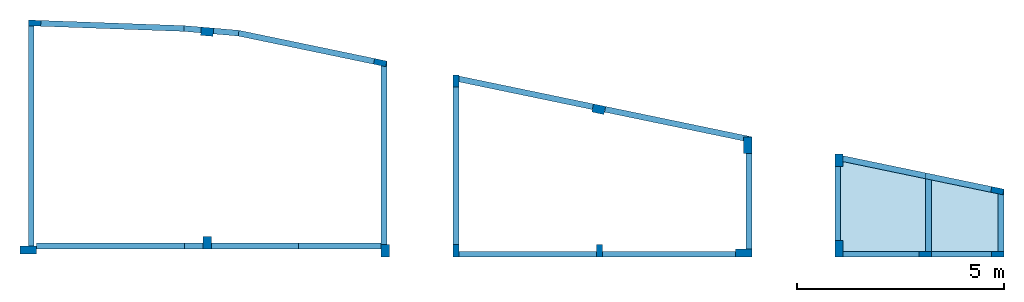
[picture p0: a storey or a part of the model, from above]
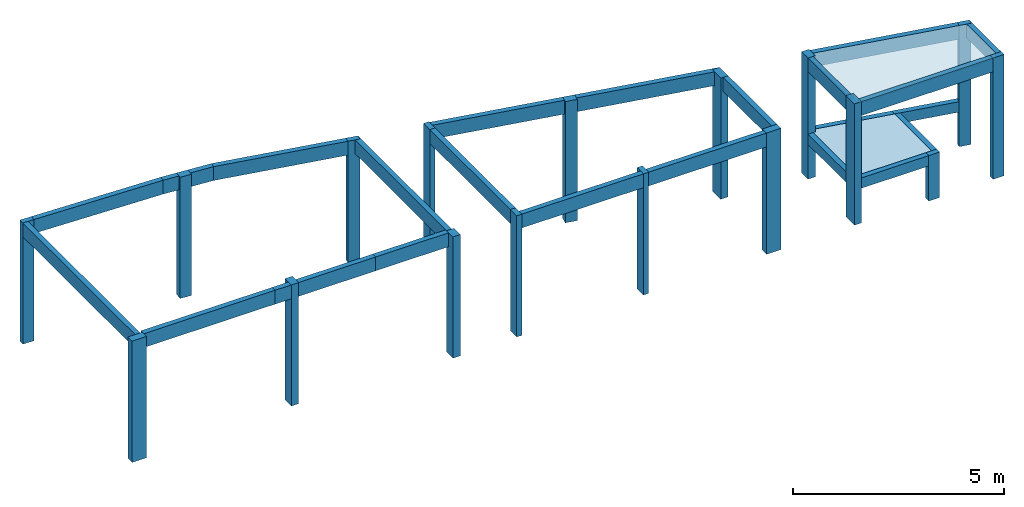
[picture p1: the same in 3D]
Properties of the parts of a building model (IFC4), part 1 of 2

# File
Description: IFC4
Time: 2026-06-03T07:09:51
Made in: IfcPlusPlus

# IfcBuildingStorey (6)
Name | LongName | Elevation (cm)
PÁTIO | PÁTIO | 0
TÉRREO | TÉRREO | 550
1º PAV. | 1º PAV. | 900
2º PAV. | 2º PAV. | 1250
3º PAV. | 3º PAV. | 1600
COBERTURA | COBERTURA | 1950

# IfcBeam (580)
Material: Concreto
Pset_ConcreteElementGeneral - ConcreteCover: 2.5 cm; ConstructionMethod: InSitu; ExposureClass: 2; StrengthClass: C-30
AltoQi_Eberick_Elemento - Elemento: Viga; Tipo: retangular
AltoQi_Eberick_Padrão - Cobrimento: 2.5 cm; Classe de concreto: C-30
AltoQi_Eberick_Cargas - Adicional (G2): 0; Solo (S): 0; Acidental (Q): 0; Água (A): 0; Subpressão (AS): 0
Pset_BeamCommon - IsExternal: yes; LoadBearing: yes
Name | In | Seção_bw (cm) | Seção_h (cm) | Elevação (cm) | Taxa de armadura | Ambiente | Cargas de parede (G2) | Reference
V.MURO1 | PÁTIO | 30 | 50 | 0 | 0.33 % | Contato com solo | 0 | Viga C-30 - Seção Retangular 30 X 50
V.MURO2 | PÁTIO | 30 | 50 | 0 | 0.33 % | Contato com solo | 0 | Viga C-30 - Seção Retangular 30 X 50
3 x V.MURO3 | PÁTIO | 30 | 50 | 0 | 0.33 % | Contato com solo | 0 | Viga C-30 - Seção Retangular 30 X 50
5 x V1 | PÁTIO | 20 | 60 | 0 | 0.20 % | Contato com solo | 1072.5 | Viga C-30 - Seção Retangular 20 X 60
V1 | PÁTIO | 20 | 60 | 0 | 0.26 % | Contato com solo | 1072.5 | Viga C-30 - Seção Retangular 20 X 60
V10 | PÁTIO | 14 | 50 | 0 | 0.22 % | Contato com solo | 1072.5 | Viga C-30 - Seção Retangular 14 X 50
4 x V11 | PÁTIO | 60 | 60 | 0 | 0.22 % | Contato com solo | 0 | Viga C-30 - Seção Retangular 60 X 60
2 x V12 | PÁTIO | 60 | 60 | 0 | 0.50 % | Contato com solo | 0 | Viga C-30 - Seção Retangular 60 X 60
V12 | PÁTIO | 60 | 60 | 0 | 0.61 % | Contato com solo | 0 | Viga C-30 - Seção Retangular 60 X 60
V12 | PÁTIO | 60 | 60 | 0 | 0.22 % | Contato com solo | 0 | Viga C-30 - Seção Retangular 60 X 60
V13 | PÁTIO | 40 | 50 | 0 | 0.40 % | Contato com solo | 1072.5 | Viga C-30 - Seção Retangular 40 X 50
V13 | PÁTIO | 40 | 50 | 0 | 0.50 % | Contato com solo | 1072.5 | Viga C-30 - Seção Retangular 40 X 50
V14 | PÁTIO | 50 | 60 | 0 | 0.16 % | Contato com solo | 0 | Viga C-30 - Seção Retangular 50 X 60
2 x V14 | PÁTIO | 50 | 60 | 0 | 0.47 % | Contato com solo | 0 | Viga C-30 - Seção Retangular 50 X 60
V15 | PÁTIO | 50 | 60 | 0 | 0.27 % | Contato com solo | 1072.5 | Viga C-30 - Seção Retangular 50 X 60
V15 | PÁTIO | 50 | 60 | 0 | 0.47 % | Contato com solo | 1072.5 | Viga C-30 - Seção Retangular 50 X 60
2 x V16 | PÁTIO | 50 | 60 | 0 | 0.47 % | Contato com solo | 0 | Viga C-30 - Seção Retangular 50 X 60
V16 | PÁTIO | 50 | 60 | 0 | 0.16 % | Contato com solo | 0 | Viga C-30 - Seção Retangular 50 X 60
V17 | PÁTIO | 14 | 50 | 0 | 0.86 % | Contato com solo | 0 | Viga C-30 - Seção Retangular 14 X 50
V18 | PÁTIO | 50 | 60 | 0 | 0.54 % | Contato com solo | 1072.5 | Viga C-30 - Seção Retangular 50 X 60
V18 | PÁTIO | 50 | 60 | 0 | 0.27 % | Contato com solo | 1072.5 | Viga C-30 - Seção Retangular 50 X 60
2 x V19 | PÁTIO | 30 | 70 | 0 | 0.48 % | Contato com solo | 0 | Viga C-30 - Seção Retangular 30 X 70
V19 | PÁTIO | 30 | 50 | 0 | 0.54 % | Contato com solo | 0 | Viga C-30 - Seção Retangular 30 X 50
V19 | PÁTIO | 30 | 70 | 0 | 0.23 % | Contato com solo | 0 | Viga C-30 - Seção Retangular 30 X 70
V2 | PÁTIO | 20 | 50 | 0 | 0.16 % | Contato com solo | 0 | Viga C-30 - Seção Retangular 20 X 50
2 x V20 | PÁTIO | 30 | 50 | 0 | 0.16 % | Contato com solo | 1072.5 | Viga C-30 - Seção Retangular 30 X 50
V20 | PÁTIO | 30 | 70 | 0 | 0.18 % | Contato com solo | 1072.5 | Viga C-30 - Seção Retangular 30 X 70
2 x V20 | PÁTIO | 30 | 70 | 0 | 0.23 % | Contato com solo | 1072.5 | Viga C-30 - Seção Retangular 30 X 70
2 x V21 | PÁTIO | 20 | 50 | 0 | 0.16 % | Contato com solo | 0 | Viga C-30 - Seção Retangular 20 X 50
2 x V22 | PÁTIO | 40 | 60 | 0 | 0.20 % | Contato com solo | 0 | Viga C-30 - Seção Retangular 40 X 60
V23 | PÁTIO | 14 | 50 | 0 | 0.22 % | Externo | 682.5 | Viga C-30 - Seção Retangular 14 X 50
V24 | PÁTIO | 20 | 170 | 0 | 0.14 % | Contato com solo | 1072.5 | Viga C-30 - Seção Retangular 20 X 170
V24 | PÁTIO | 20 | 80 | 0 | 0.15 % | Contato com solo | 1072.5 | Viga C-30 - Seção Retangular 20 X 80
2 x V25 | PÁTIO | 40 | 60 | 0 | 0.59 % | Contato com solo | 0 | Viga C-30 - Seção Retangular 40 X 60
V25 | PÁTIO | 40 | 60 | 0 | 0.34 % | Contato com solo | 0 | Viga C-30 - Seção Retangular 40 X 60
2 x V26 | PÁTIO | 20 | 60 | 0 | 0.41 % | Contato com solo | 0 | Viga C-30 - Seção Retangular 20 X 60
V27 | PÁTIO | 20 | 170 | 0 | 0.16 % | Contato com solo | 1072.5 | Viga C-30 - Seção Retangular 20 X 170
2 x V28 | PÁTIO | 50 | 60 | 0 | 0.67 % | Contato com solo | 0 | Viga C-30 - Seção Retangular 50 X 60
V28 | PÁTIO | 50 | 60 | 0 | 0.16 % | Contato com solo | 0 | Viga C-30 - Seção Retangular 50 X 60
V28 | PÁTIO | 50 | 60 | 0 | 0.27 % | Contato com solo | 0 | Viga C-30 - Seção Retangular 50 X 60
V29 | PÁTIO | 50 | 60 | 0 | 0.16 % | Contato com solo | 0 | Viga C-30 - Seção Retangular 50 X 60
2 x V29 | PÁTIO | 50 | 60 | 0 | 0.47 % | Contato com solo | 0 | Viga C-30 - Seção Retangular 50 X 60
V29 | PÁTIO | 50 | 60 | 0 | 0.27 % | Contato com solo | 0 | Viga C-30 - Seção Retangular 50 X 60
2 x V3 | PÁTIO | 20 | 170 | 0 | 0.35 % | Contato com solo | 1072.5 | Viga C-30 - Seção Retangular 20 X 170
V3 | PÁTIO | 20 | 70 | 0 | 0.43 % | Contato com solo | 1072.5 | Viga C-30 - Seção Retangular 20 X 70
V3 | PÁTIO | 20 | 70 | 0 | 0.29 % | Contato com solo | 1072.5 | Viga C-30 - Seção Retangular 20 X 70
V3 | PÁTIO | 20 | 50 | 0 | 0.40 % | Contato com solo | 1072.5 | Viga C-30 - Seção Retangular 20 X 50
V30 | PÁTIO | 70 | 60 | 0 | 0.29 % | Contato com solo | 0 | Viga C-30 - Seção Retangular 70 X 60
V30 | PÁTIO | 70 | 60 | 0 | 0.53 % | Contato com solo | 0 | Viga C-30 - Seção Retangular 70 X 60
2 x V31 | PÁTIO | 20 | 50 | 0 | 0.40 % | Contato com solo | 1072.5 | Viga C-30 - Seção Retangular 20 X 50
V31 | PÁTIO | 20 | 170 | 0 | 0.18 % | Contato com solo | 1072.5 | Viga C-30 - Seção Retangular 20 X 170
V32 | PÁTIO | 14 | 50 | 0 | 0.22 % | Contato com solo | 1072.5 | Viga C-30 - Seção Retangular 14 X 50
V33 | PÁTIO | 60 | 60 | 0 | 0.45 % | Contato com solo | 0 | Viga C-30 - Seção Retangular 60 X 60
V33 | PÁTIO | 60 | 60 | 0 | 0.22 % | Contato com solo | 0 | Viga C-30 - Seção Retangular 60 X 60
3 x V34 | PÁTIO | 14 | 50 | 0 | 0.35 % | Contato com solo | 1072.5 | Viga C-30 - Seção Retangular 14 X 50
2 x V4 | PÁTIO | 20 | 50 | 0 | 0.24 % | Contato com solo | 0 | Viga C-30 - Seção Retangular 20 X 50
V4 | PÁTIO | 20 | 50 | 0 | 0.16 % | Contato com solo | 0 | Viga C-30 - Seção Retangular 20 X 50
V5 | PÁTIO | 14 | 50 | 0 | 0.22 % | Contato com solo | 0 | Viga C-30 - Seção Retangular 14 X 50
3 x V6 | PÁTIO | 14 | 50 | 0 | 0.22 % | Contato com solo | 0 | Viga C-30 - Seção Retangular 14 X 50
V6 | PÁTIO | 14 | 50 | 0 | 0.34 % | Contato com solo | 0 | Viga C-30 - Seção Retangular 14 X 50
2 x V7 | PÁTIO | 14 | 50 | 0 | 0.22 % | Contato com solo | 0 | Viga C-30 - Seção Retangular 14 X 50
V8 | PÁTIO | 14 | 50 | 0 | 0.22 % | Contato com solo | 0 | Viga C-30 - Seção Retangular 14 X 50
2 x V9 | PÁTIO | 14 | 50 | 0 | 0.22 % | Externo | 682.5 | Viga C-30 - Seção Retangular 14 X 50
2 x V.ESCADA1 | TÉRREO | 14 | 50 | 0 | 0.22 % | Contato com solo | 585 | Viga C-30 - Seção Retangular 14 X 50
V.ESCADA2 | TÉRREO | 14 | 50 | 0 | 0.22 % | Contato com solo | 585 | Viga C-30 - Seção Retangular 14 X 50
2 x V.MURO1 | TÉRREO | 20 | 60 | 0 | 0.20 % | Externo | 585 | Viga C-30 - Seção Retangular 20 X 60
V.MURO2 | TÉRREO | 20 | 50 | 0 | 0.16 % | Externo | 585 | Viga C-30 - Seção Retangular 20 X 50
2 x V.MURO3 | TÉRREO | 20 | 50 | 0 | 0.40 % | Externo | 0 | Viga C-30 - Seção Retangular 20 X 50
V.MURO4 | TÉRREO | 20 | 50 | 0 | 0.40 % | Externo | 0 | Viga C-30 - Seção Retangular 20 X 50
V.RAMPA1 | TÉRREO | 20 | 50 | 0 | 0.16 % | Externo | 0 | Viga C-30 - Seção Retangular 20 X 50
V.RAMPA10 | TÉRREO | 20 | 40 | 0 | 0.20 % | Externo | 0 | Viga C-30 - Seção Retangular 20 X 40
2 x V.RAMPA11 | TÉRREO | 20 | 50 | 0 | 0.31 % | Externo | 585 | Viga C-30 - Seção Retangular 20 X 50
2 x V.RAMPA11 | TÉRREO | 20 | 40 | 0 | 0.39 % | Externo | 0 | Viga C-30 - Seção Retangular 20 X 40
V.RAMPA12 | TÉRREO | 20 | 40 | 0 | 0.20 % | Externo | 0 | Viga C-30 - Seção Retangular 20 X 40
2 x V.RAMPA13 | TÉRREO | 20 | 50 | 0 | 0.49 % | Externo | 0 | Viga C-30 - Seção Retangular 20 X 50
V.RAMPA2 | TÉRREO | 20 | 50 | 0 | 0.31 % | Externo | 0 | Viga C-30 - Seção Retangular 20 X 50
2 x V.RAMPA3 | TÉRREO | 40 | 25 | 0 | 0.49 % | Externo | 0 | Viga C-30 - Seção Retangular 40 X 25
V.RAMPA4 | TÉRREO | 20 | 50 | 0 | 0.24 % | Externo | 0 | Viga C-30 - Seção Retangular 20 X 50
V.RAMPA5 | TÉRREO | 20 | 40 | 0 | 0.39 % | Externo | 0 | Viga C-30 - Seção Retangular 20 X 40
2 x V.RAMPA6 | TÉRREO | 20 | 40 | 0 | 0.29 % | Externo | 0 | Viga C-30 - Seção Retangular 20 X 40
2 x V.RAMPA7 | TÉRREO | 20 | 50 | 0 | 0.24 % | Externo | 0 | Viga C-30 - Seção Retangular 20 X 50
3 x V.RAMPA8 | TÉRREO | 20 | 50 | 0 | 0.37 % | Externo | 0 | Viga C-30 - Seção Retangular 20 X 50
V.RAMPA9 | TÉRREO | 20 | 40 | 0 | 0.20 % | Externo | 0 | Viga C-30 - Seção Retangular 20 X 40
V1 | TÉRREO | 14 | 50 | 0 | 0.22 % | Externo | 682.5 | Viga C-30 - Seção Retangular 14 X 50
4 x V10 | TÉRREO | 20 | 50 | 0 | 0.60 % | Externo | 0 | Viga C-30 - Seção Retangular 20 X 50
V11 | TÉRREO | 25 | 50 | 0 | 0.29 % | Externo | 682.5 | Viga C-30 - Seção Retangular 25 X 50
V11 | TÉRREO | 25 | 50 | 0 | 0.39 % | Externo | 682.5 | Viga C-30 - Seção Retangular 25 X 50
V11 | TÉRREO | 14 | 50 | 0 | 0.35 % | Externo | 682.5 | Viga C-30 - Seção Retangular 14 X 50
V12 | TÉRREO | 14 | 50 | 0 | 0.22 % | Externo | 682.5 | Viga C-30 - Seção Retangular 14 X 50
V13 | TÉRREO | 14 | 50 | 0 | 0.22 % | Externo | 682.5 | Viga C-30 - Seção Retangular 14 X 50
V14 | TÉRREO | 14 | 50 | 0 | 0.22 % | Externo | 682.5 | Viga C-30 - Seção Retangular 14 X 50
V15 | TÉRREO | 20 | 50 | 0 | 0.37 % | Externo | 0 | Viga C-30 - Seção Retangular 20 X 50
V15 | TÉRREO | 20 | 50 | 0 | 0.37 % | Externo | 682.5 | Viga C-30 - Seção Retangular 20 X 50
V16 | TÉRREO | 14 | 50 | 0 | 0.22 % | Externo | 682.5 | Viga C-30 - Seção Retangular 14 X 50
V17 | TÉRREO | 14 | 50 | 0 | 0.22 % | Externo | 682.5 | Viga C-30 - Seção Retangular 14 X 50
3 x V18 | TÉRREO | 14 | 50 | 0 | 0.35 % | Externo | 682.5 | Viga C-30 - Seção Retangular 14 X 50
V18 | TÉRREO | 14 | 50 | 0 | 0.53 % | Externo | 682.5 | Viga C-30 - Seção Retangular 14 X 50
V18 | TÉRREO | 14 | 50 | 0 | 0.70 % | Externo | 682.5 | Viga C-30 - Seção Retangular 14 X 50
V19 | TÉRREO | 14 | 50 | 0 | 0.22 % | Externo | 682.5 | Viga C-30 - Seção Retangular 14 X 50
2 x V2 | TÉRREO | 14 | 50 | 0 | 0.53 % | Externo | 682.5 | Viga C-30 - Seção Retangular 14 X 50
V20 | TÉRREO | 14 | 50 | 0 | 0.22 % | Externo | 682.5 | Viga C-30 - Seção Retangular 14 X 50
V21 | TÉRREO | 14 | 50 | 0 | 0.22 % | Externo | 682.5 | Viga C-30 - Seção Retangular 14 X 50
2 x V22 | TÉRREO | 14 | 50 | 0 | 0.22 % | Externo | 0 | Viga C-30 - Seção Retangular 14 X 50
2 x V23 | TÉRREO | 14 | 50 | 0 | 0.34 % | Externo | 682.5 | Viga C-30 - Seção Retangular 14 X 50
V23 | TÉRREO | 14 | 50 | 0 | 0.22 % | Externo | 682.5 | Viga C-30 - Seção Retangular 14 X 50
V24 | TÉRREO | 14 | 50 | 0 | 0.34 % | Externo | 682.5 | Viga C-30 - Seção Retangular 14 X 50
2 x V25 | TÉRREO | 14 | 50 | 0 | 0.53 % | Externo | 682.5 | Viga C-30 - Seção Retangular 14 X 50
2 x V26 | TÉRREO | 14 | 50 | 0 | 0.53 % | Externo | 682.5 | Viga C-30 - Seção Retangular 14 X 50
3 x V27 | TÉRREO | 14 | 50 | 0 | 0.53 % | Externo | 682.5 | Viga C-30 - Seção Retangular 14 X 50
2 x V28 | TÉRREO | 14 | 50 | 0 | 0.53 % | Externo | 682.5 | Viga C-30 - Seção Retangular 14 X 50
V29 | TÉRREO | 14 | 50 | 0 | 0.35 % | Externo | 682.5 | Viga C-30 - Seção Retangular 14 X 50
3 x V3 | TÉRREO | 20 | 50 | 0 | 0.37 % | Externo | 682.5 | Viga C-30 - Seção Retangular 20 X 50
V3 | TÉRREO | 20 | 50 | 0 | 0.24 % | Externo | 682.5 | Viga C-30 - Seção Retangular 20 X 50
V3 | TÉRREO | 20 | 50 | 0 | 0.16 % | Externo | 682.5 | Viga C-30 - Seção Retangular 20 X 50
2 x V3 | TÉRREO | 20 | 50 | 0 | 0.25 % | Externo | 682.5 | Viga C-30 - Seção Retangular 20 X 50
2 x V30 | TÉRREO | 20 | 50 | 0 | 0.16 % | Externo | 682.5 | Viga C-30 - Seção Retangular 20 X 50
2 x V30 | TÉRREO | 20 | 50 | 0 | 0.24 % | Externo | 682.5 | Viga C-30 - Seção Retangular 20 X 50
2 x V31 | TÉRREO | 20 | 50 | 0 | 0.37 % | Externo | 0 | Viga C-30 - Seção Retangular 20 X 50
V31 | TÉRREO | 20 | 50 | 0 | 0.25 % | Externo | 0 | Viga C-30 - Seção Retangular 20 X 50
V32 | TÉRREO | 14 | 50 | 0 | 0.22 % | Externo | 0 | Viga C-30 - Seção Retangular 14 X 50
V33 | TÉRREO | 14 | 50 | 0 | 0.22 % | Externo | 682.5 | Viga C-30 - Seção Retangular 14 X 50
V34 | TÉRREO | 14 | 50 | 0 | 0.22 % | Externo | 682.5 | Viga C-30 - Seção Retangular 14 X 50
V34 | TÉRREO | 14 | 50 | 0 | 0.34 % | Externo | 682.5 | Viga C-30 - Seção Retangular 14 X 50
V35 | TÉRREO | 14 | 50 | 0 | 0.86 % | Externo | 682.5 | Viga C-30 - Seção Retangular 14 X 50
2 x V36 | TÉRREO | 14 | 50 | 0 | 0.86 % | Externo | 682.5 | Viga C-30 - Seção Retangular 14 X 50
2 x V36 | TÉRREO | 14 | 50 | 0 | 0.53 % | Externo | 682.5 | Viga C-30 - Seção Retangular 14 X 50
V37 | TÉRREO | 14 | 50 | 0 | 0.22 % | Externo | 682.5 | Viga C-30 - Seção Retangular 14 X 50
V38 | TÉRREO | 14 | 50 | 0 | 0.22 % | Externo | 682.5 | Viga C-30 - Seção Retangular 14 X 50
V39 | TÉRREO | 14 | 50 | 0 | 0.22 % | Externo | 682.5 | Viga C-30 - Seção Retangular 14 X 50
V4 | TÉRREO | 14 | 50 | 0 | 0.22 % | Externo | 0 | Viga C-30 - Seção Retangular 14 X 50
4 x V40 | TÉRREO | 14 | 50 | 0 | 0.53 % | Externo | 682.5 | Viga C-30 - Seção Retangular 14 X 50
V41 | TÉRREO | 14 | 50 | 0 | 0.35 % | Externo | 682.5 | Viga C-30 - Seção Retangular 14 X 50
6 x V41 | TÉRREO | 14 | 50 | 0 | 0.70 % | Externo | 682.5 | Viga C-30 - Seção Retangular 14 X 50
2 x V42 | TÉRREO | 14 | 50 | 0 | 0.53 % | Externo | 682.5 | Viga C-30 - Seção Retangular 14 X 50
V42 | TÉRREO | 14 | 50 | 0 | 0.35 % | Externo | 682.5 | Viga C-30 - Seção Retangular 14 X 50
4 x V42 | TÉRREO | 14 | 50 | 0 | 0.22 % | Externo | 682.5 | Viga C-30 - Seção Retangular 14 X 50
3 x V43 | TÉRREO | 14 | 50 | 0 | 0.22 % | Externo | 682.5 | Viga C-30 - Seção Retangular 14 X 50
V43 | TÉRREO | 14 | 50 | 0 | 0.34 % | Externo | 682.5 | Viga C-30 - Seção Retangular 14 X 50
V44 | TÉRREO | 30 | 50 | 0 | 0.16 % | Externo | 0 | Viga C-30 - Seção Retangular 30 X 50
2 x V44 | TÉRREO | 30 | 50 | 0 | 0.33 % | Externo | 0 | Viga C-30 - Seção Retangular 30 X 50
5 x V45 | TÉRREO | 14 | 50 | 0 | 0.35 % | Externo | 682.5 | Viga C-30 - Seção Retangular 14 X 50
3 x V5 | TÉRREO | 20 | 50 | 0 | 0.37 % | Externo | 682.5 | Viga C-30 - Seção Retangular 20 X 50
2 x V5 | TÉRREO | 20 | 50 | 0 | 0.25 % | Externo | 682.5 | Viga C-30 - Seção Retangular 20 X 50
2 x V6 | TÉRREO | 14 | 50 | 0 | 0.22 % | Externo | 682.5 | Viga C-30 - Seção Retangular 14 X 50
2 x V7 | TÉRREO | 14 | 50 | 0 | 0.86 % | Externo | 682.5 | Viga C-30 - Seção Retangular 14 X 50
2 x V8 | TÉRREO | 14 | 50 | 0 | 0.53 % | Externo | 0 | Viga C-30 - Seção Retangular 14 X 50
2 x V9 | TÉRREO | 14 | 50 | 0 | 0.22 % | Externo | 0 | Viga C-30 - Seção Retangular 14 X 50
2 x V.ESCADA1 | 1º PAV. | 14 | 50 | 0 | 0.22 % | Externo | 585 | Viga C-30 - Seção Retangular 14 X 50
V.ESCADA2 | 1º PAV. | 14 | 50 | 0 | 0.22 % | Externo | 0 | Viga C-30 - Seção Retangular 14 X 50
V.MURO1 | 1º PAV. | 14 | 40 | -100 | 0.28 % | Externo | 0 | Viga C-30 - Seção Retangular 14 X 40
V.MURO2 | 1º PAV. | 14 | 40 | -100 | 0.28 % | Externo | 0 | Viga C-30 - Seção Retangular 14 X 40
V.MURO3 | 1º PAV. | 20 | 60 | -40 | 0.51 % | Externo | 0 | Viga C-30 - Seção Retangular 20 X 60
V.MURO4 | 1º PAV. | 14 | 40 | -100 | 0.28 % | Externo | 585 | Viga C-30 - Seção Retangular 14 X 40
V.MURO5 | 1º PAV. | 14 | 40 | -100 | 0.28 % | Externo | 0 | Viga C-30 - Seção Retangular 14 X 40
V1 | 1º PAV. | 14 | 50 | 0 | 0.22 % | Externo | 682.5 | Viga C-30 - Seção Retangular 14 X 50
V10 | 1º PAV. | 20 | 50 | 0 | 0.49 % | Externo | 682.5 | Viga C-30 - Seção Retangular 20 X 50
V10 | 1º PAV. | 20 | 50 | 0 | 0.37 % | Externo | 682.5 | Viga C-30 - Seção Retangular 20 X 50
V11 | 1º PAV. | 14 | 50 | 0 | 0.22 % | Externo | 682.5 | Viga C-30 - Seção Retangular 14 X 50
V12 | 1º PAV. | 14 | 50 | 0 | 0.22 % | Externo | 0 | Viga C-30 - Seção Retangular 14 X 50
V13 | 1º PAV. | 20 | 50 | 0 | 0.37 % | Externo | 682.5 | Viga C-30 - Seção Retangular 20 X 50
3 x V13 | 1º PAV. | 20 | 50 | 0 | 0.49 % | Externo | 0 | Viga C-30 - Seção Retangular 20 X 50
V13 | 1º PAV. | 20 | 50 | 0 | 0.37 % | Externo | 0 | Viga C-30 - Seção Retangular 20 X 50
V13 | 1º PAV. | 20 | 50 | 0 | 0.25 % | Externo | 682.5 | Viga C-30 - Seção Retangular 20 X 50
V14 | 1º PAV. | 14 | 50 | 0 | 0.22 % | Externo | 682.5 | Viga C-30 - Seção Retangular 14 X 50
V15 | 1º PAV. | 14 | 70 | 0 | 0.16 % | Externo | 682.5 | Viga C-30 - Seção Retangular 14 X 70
V16 | 1º PAV. | 14 | 50 | 0 | 0.22 % | Externo | 682.5 | Viga C-30 - Seção Retangular 14 X 50
V17 | 1º PAV. | 14 | 70 | 0 | 0.16 % | Externo | 682.5 | Viga C-30 - Seção Retangular 14 X 70
V18 | 1º PAV. | 14 | 50 | 0 | 0.22 % | Externo | 682.5 | Viga C-30 - Seção Retangular 14 X 50
V19 | 1º PAV. | 14 | 50 | 0 | 0.53 % | Externo | 682.5 | Viga C-30 - Seção Retangular 14 X 50
V19 | 1º PAV. | 14 | 50 | 0 | 0.53 % | Externo | 0 | Viga C-30 - Seção Retangular 14 X 50
V2 | 1º PAV. | 20 | 50 | 0 | 0.37 % | Externo | 682.5 | Viga C-30 - Seção Retangular 20 X 50
V2 | 1º PAV. | 20 | 70 | 0 | 0.18 % | Externo | 682.5 | Viga C-30 - Seção Retangular 20 X 70
V20 | 1º PAV. | 14 | 50 | 0 | 0.22 % | Externo | 682.5 | Viga C-30 - Seção Retangular 14 X 50
V21 | 1º PAV. | 14 | 70 | 0 | 0.16 % | Externo | 682.5 | Viga C-30 - Seção Retangular 14 X 70
V22 | 1º PAV. | 14 | 50 | 0 | 0.22 % | Externo | 682.5 | Viga C-30 - Seção Retangular 14 X 50
V23 | 1º PAV. | 14 | 70 | 0 | 0.16 % | Externo | 682.5 | Viga C-30 - Seção Retangular 14 X 70
V24 | 1º PAV. | 20 | 70 | 0 | 0.17 % | Externo | 682.5 | Viga C-30 - Seção Retangular 20 X 70
V24 | 1º PAV. | 20 | 50 | 0 | 0.24 % | Externo | 682.5 | Viga C-30 - Seção Retangular 20 X 50
V24 | 1º PAV. | 20 | 50 | 0 | 0.37 % | Externo | 682.5 | Viga C-30 - Seção Retangular 20 X 50
V25 | 1º PAV. | 14 | 50 | 0 | 0.57 % | Externo | 682.5 | Viga C-30 - Seção Retangular 14 X 50
V25 | 1º PAV. | 14 | 50 | 0 | 0.53 % | Externo | 682.5 | Viga C-30 - Seção Retangular 14 X 50
V26 | 1º PAV. | 14 | 50 | 0 | 0.22 % | Externo | 682.5 | Viga C-30 - Seção Retangular 14 X 50
V27 | 1º PAV. | 14 | 50 | 0 | 0.22 % | Externo | 682.5 | Viga C-30 - Seção Retangular 14 X 50
8 x V28 | 1º PAV. | 20 | 70 | 0 | 0.86 % | Externo | 682.5 | Viga C-30 - Seção Retangular 20 X 70
3 x V29 | 1º PAV. | 40 | 60 | 0 | 0.20 % | Externo | 0 | Viga C-30 - Seção Retangular 40 X 60
4 x V3 | 1º PAV. | 20 | 50 | 0 | 0.25 % | Externo | 682.5 | Viga C-30 - Seção Retangular 20 X 50
3 x V3 | 1º PAV. | 20 | 50 | 0 | 0.37 % | Externo | 682.5 | Viga C-30 - Seção Retangular 20 X 50
2 x V30 | 1º PAV. | 14 | 50 | 0 | 0.34 % | Externo | 682.5 | Viga C-30 - Seção Retangular 14 X 50
V31 | 1º PAV. | 14 | 50 | 0 | 0.34 % | Externo | 682.5 | Viga C-30 - Seção Retangular 14 X 50
2 x V32 | 1º PAV. | 14 | 50 | 0 | 0.45 % | Externo | 682.5 | Viga C-30 - Seção Retangular 14 X 50
2 x V33 | 1º PAV. | 14 | 50 | 0 | 0.53 % | Externo | 682.5 | Viga C-30 - Seção Retangular 14 X 50
3 x V34 | 1º PAV. | 14 | 50 | 0 | 0.53 % | Externo | 682.5 | Viga C-30 - Seção Retangular 14 X 50
2 x V35 | 1º PAV. | 14 | 50 | 0 | 0.53 % | Externo | 682.5 | Viga C-30 - Seção Retangular 14 X 50
V36 | 1º PAV. | 14 | 50 | 0 | 0.22 % | Externo | 682.5 | Viga C-30 - Seção Retangular 14 X 50
2 x V37 | 1º PAV. | 20 | 50 | 0 | 0.24 % | Externo | 682.5 | Viga C-30 - Seção Retangular 20 X 50
V37 | 1º PAV. | 20 | 50 | 0 | 0.16 % | Externo | 682.5 | Viga C-30 - Seção Retangular 20 X 50
3 x V38 | 1º PAV. | 20 | 50 | 0 | 0.25 % | Externo | 0 | Viga C-30 - Seção Retangular 20 X 50
V39 | 1º PAV. | 14 | 50 | 0 | 0.22 % | Externo | 0 | Viga C-30 - Seção Retangular 14 X 50
V4 | 1º PAV. | 14 | 50 | 0 | 0.22 % | Externo | 0 | Viga C-30 - Seção Retangular 14 X 50
V40 | 1º PAV. | 14 | 50 | 0 | 0.22 % | Externo | 682.5 | Viga C-30 - Seção Retangular 14 X 50
V41 | 1º PAV. | 14 | 50 | 0 | 0.22 % | Externo | 682.5 | Viga C-30 - Seção Retangular 14 X 50
V42 | 1º PAV. | 14 | 50 | 0 | 0.53 % | Externo | 682.5 | Viga C-30 - Seção Retangular 14 X 50
V43 | 1º PAV. | 14 | 50 | 0 | 0.34 % | Externo | 682.5 | Viga C-30 - Seção Retangular 14 X 50
2 x V43 | 1º PAV. | 14 | 50 | 0 | 0.45 % | Externo | 682.5 | Viga C-30 - Seção Retangular 14 X 50
V44 | 1º PAV. | 14 | 50 | 0 | 0.22 % | Externo | 682.5 | Viga C-30 - Seção Retangular 14 X 50
V45 | 1º PAV. | 14 | 50 | 0 | 0.22 % | Externo | 682.5 | Viga C-30 - Seção Retangular 14 X 50
V46 | 1º PAV. | 14 | 50 | 0 | 0.22 % | Externo | 682.5 | Viga C-30 - Seção Retangular 14 X 50
2 x V47 | 1º PAV. | 14 | 50 | 0 | 0.53 % | Externo | 682.5 | Viga C-30 - Seção Retangular 14 X 50
2 x V47 | 1º PAV. | 14 | 50 | 0 | 0.35 % | Externo | 682.5 | Viga C-30 - Seção Retangular 14 X 50
6 x V48 | 1º PAV. | 14 | 50 | 0 | 0.70 % | Externo | 682.5 | Viga C-30 - Seção Retangular 14 X 50
V48 | 1º PAV. | 14 | 50 | 0 | 0.35 % | Externo | 682.5 | Viga C-30 - Seção Retangular 14 X 50
4 x V49 | 1º PAV. | 14 | 50 | 0 | 0.22 % | Externo | 682.5 | Viga C-30 - Seção Retangular 14 X 50
2 x V49 | 1º PAV. | 14 | 50 | 0 | 0.53 % | Externo | 682.5 | Viga C-30 - Seção Retangular 14 X 50
V49 | 1º PAV. | 14 | 50 | 0 | 0.35 % | Externo | 682.5 | Viga C-30 - Seção Retangular 14 X 50
5 x V5 | 1º PAV. | 20 | 50 | 0 | 0.16 % | Externo | 682.5 | Viga C-30 - Seção Retangular 20 X 50
4 x V50 | 1º PAV. | 14 | 50 | 0 | 0.34 % | Externo | 682.5 | Viga C-30 - Seção Retangular 14 X 50
V51 | 1º PAV. | 30 | 50 | 0 | 0.33 % | Externo | 0 | Viga C-30 - Seção Retangular 30 X 50
2 x V51 | 1º PAV. | 30 | 50 | 0 | 0.16 % | Externo | 0 | Viga C-30 - Seção Retangular 30 X 50
4 x V52 | 1º PAV. | 14 | 50 | 0 | 0.35 % | Externo | 682.5 | Viga C-30 - Seção Retangular 14 X 50
V52 | 1º PAV. | 14 | 50 | 0 | 0.22 % | Externo | 682.5 | Viga C-30 - Seção Retangular 14 X 50
V6 | 1º PAV. | 14 | 70 | 0 | 0.16 % | Externo | 682.5 | Viga C-30 - Seção Retangular 14 X 70
V7 | 1º PAV. | 14 | 70 | 0 | 0.16 % | Externo | 682.5 | Viga C-30 - Seção Retangular 14 X 70
V8 | 1º PAV. | 14 | 70 | 0 | 0.16 % | Externo | 682.5 | Viga C-30 - Seção Retangular 14 X 70
3 x V9 | 1º PAV. | 14 | 50 | 0 | 0.53 % | Externo | 0 | Viga C-30 - Seção Retangular 14 X 50
2 x V.ESCADA1 | 2º PAV. | 14 | 50 | 0 | 0.22 % | Externo | 585 | Viga C-30 - Seção Retangular 14 X 50
V.ESCADA2 | 2º PAV. | 14 | 50 | 0 | 0.22 % | Externo | 585 | Viga C-30 - Seção Retangular 14 X 50
V.INCLINADA1 | 2º PAV. | 20 | 50 | 0 | 0.31 % | Externo | 0 | Viga C-30 - Seção Retangular 20 X 50
V.INCLINADA2 | 2º PAV. | 20 | 50 | 0 | 0.31 % | Externo | 0 | Viga C-30 - Seção Retangular 20 X 50
V1 | 2º PAV. | 14 | 50 | 0 | 0.22 % | Externo | 682.5 | Viga C-30 - Seção Retangular 14 X 50
V10 | 2º PAV. | 20 | 50 | 0 | 0.49 % | Externo | 682.5 | Viga C-30 - Seção Retangular 20 X 50
V10 | 2º PAV. | 20 | 50 | 0 | 0.37 % | Externo | 682.5 | Viga C-30 - Seção Retangular 20 X 50
V11 | 2º PAV. | 14 | 50 | 0 | 0.22 % | Externo | 682.5 | Viga C-30 - Seção Retangular 14 X 50
V12 | 2º PAV. | 14 | 50 | 0 | 0.22 % | Externo | 0 | Viga C-30 - Seção Retangular 14 X 50
2 x V13 | 2º PAV. | 25 | 50 | 0 | 0.32 % | Externo | 0 | Viga C-30 - Seção Retangular 25 X 50
4 x V13 | 2º PAV. | 25 | 50 | 0 | 0.48 % | Externo | 0 | Viga C-30 - Seção Retangular 25 X 50
V14 | 2º PAV. | 14 | 50 | 0 | 0.22 % | Externo | 682.5 | Viga C-30 - Seção Retangular 14 X 50
V15 | 2º PAV. | 14 | 50 | 0 | 0.22 % | Externo | 682.5 | Viga C-30 - Seção Retangular 14 X 50
V16 | 2º PAV. | 14 | 50 | 0 | 0.22 % | Externo | 682.5 | Viga C-30 - Seção Retangular 14 X 50
V17 | 2º PAV. | 14 | 50 | 0 | 0.22 % | Externo | 682.5 | Viga C-30 - Seção Retangular 14 X 50
V18 | 2º PAV. | 14 | 50 | 0 | 0.22 % | Externo | 682.5 | Viga C-30 - Seção Retangular 14 X 50
V19 | 2º PAV. | 14 | 50 | 0 | 0.45 % | Externo | 0 | Viga C-30 - Seção Retangular 14 X 50
V19 | 2º PAV. | 14 | 50 | 0 | 0.45 % | Externo | 682.5 | Viga C-30 - Seção Retangular 14 X 50
V2 | 2º PAV. | 20 | 50 | 0 | 0.49 % | Externo | 682.5 | Viga C-30 - Seção Retangular 20 X 50
2 x V2 | 2º PAV. | 20 | 50 | 0 | 0.86 % | Externo | 682.5 | Viga C-30 - Seção Retangular 20 X 50
V20 | 2º PAV. | 14 | 50 | 0 | 0.22 % | Externo | 682.5 | Viga C-30 - Seção Retangular 14 X 50
V21 | 2º PAV. | 14 | 50 | 0 | 0.22 % | Externo | 682.5 | Viga C-30 - Seção Retangular 14 X 50
V22 | 2º PAV. | 14 | 50 | 0 | 0.22 % | Externo | 682.5 | Viga C-30 - Seção Retangular 14 X 50
4 x V23 | 2º PAV. | 20 | 50 | 0 | 0.80 % | Externo | 682.5 | Viga C-30 - Seção Retangular 20 X 50
V23 | 2º PAV. | 20 | 50 | 0 | 0.40 % | Externo | 682.5 | Viga C-30 - Seção Retangular 20 X 50
V23 | 2º PAV. | 20 | 50 | 0 | 0.60 % | Externo | 682.5 | Viga C-30 - Seção Retangular 20 X 50
2 x V24 | 2º PAV. | 14 | 50 | 0 | 0.70 % | Externo | 682.5 | Viga C-30 - Seção Retangular 14 X 50
V25 | 2º PAV. | 14 | 50 | 0 | 0.22 % | Externo | 682.5 | Viga C-30 - Seção Retangular 14 X 50
V26 | 2º PAV. | 14 | 50 | 0 | 0.22 % | Externo | 682.5 | Viga C-30 - Seção Retangular 14 X 50
8 x V27 | 2º PAV. | 14 | 50 | 0 | 0.53 % | Externo | 682.5 | Viga C-30 - Seção Retangular 14 X 50
2 x V28 | 2º PAV. | 14 | 50 | 0 | 0.53 % | Externo | 0 | Viga C-30 - Seção Retangular 14 X 50
V29 | 2º PAV. | 14 | 50 | 0 | 0.35 % | Externo | 0 | Viga C-30 - Seção Retangular 14 X 50
V29 | 2º PAV. | 14 | 50 | 0 | 0.53 % | Externo | 0 | Viga C-30 - Seção Retangular 14 X 50
4 x V3 | 2º PAV. | 20 | 50 | 0 | 0.37 % | Externo | 682.5 | Viga C-30 - Seção Retangular 20 X 50
2 x V3 | 2º PAV. | 20 | 70 | 0 | 0.26 % | Externo | 682.5 | Viga C-30 - Seção Retangular 20 X 70
2 x V3 | 2º PAV. | 20 | 50 | 0 | 0.25 % | Externo | 682.5 | Viga C-30 - Seção Retangular 20 X 50
V30 | 2º PAV. | 14 | 50 | 0 | 0.53 % | Externo | 682.5 | Viga C-30 - Seção Retangular 14 X 50
2 x V31 | 2º PAV. | 20 | 50 | 0 | 0.16 % | Externo | 0 | Viga C-30 - Seção Retangular 20 X 50
2 x V32 | 2º PAV. | 25 | 60 | 0 | 0.54 % | Externo | 682.5 | Viga C-30 - Seção Retangular 25 X 60
V33 | 2º PAV. | 14 | 50 | 0 | 1.15 % | Externo | 0 | Viga C-30 - Seção Retangular 14 X 50
V33 | 2º PAV. | 14 | 50 | 0 | 1.15 % | Externo | 682.5 | Viga C-30 - Seção Retangular 14 X 50
2 x V34 | 2º PAV. | 14 | 50 | 0 | 0.45 % | Externo | 682.5 | Viga C-30 - Seção Retangular 14 X 50
2 x V35 | 2º PAV. | 14 | 50 | 0 | 0.86 % | Externo | 0 | Viga C-30 - Seção Retangular 14 X 50
V35 | 2º PAV. | 14 | 50 | 0 | 0.86 % | Externo | 682.5 | Viga C-30 - Seção Retangular 14 X 50
2 x V36 | 2º PAV. | 14 | 50 | 0 | 0.45 % | Externo | 682.5 | Viga C-30 - Seção Retangular 14 X 50
V37 | 2º PAV. | 14 | 50 | 0 | 0.22 % | Externo | 682.5 | Viga C-30 - Seção Retangular 14 X 50
2 x V38 | 2º PAV. | 20 | 50 | 0 | 0.24 % | Externo | 682.5 | Viga C-30 - Seção Retangular 20 X 50
V38 | 2º PAV. | 20 | 50 | 0 | 0.16 % | Externo | 0 | Viga C-30 - Seção Retangular 20 X 50
V39 | 2º PAV. | 20 | 50 | 0 | 0.16 % | Contato com solo | 0 | Viga C-30 - Seção Retangular 20 X 50
2 x V39 | 2º PAV. | 20 | 50 | 0 | 0.31 % | Contato com solo | 0 | Viga C-30 - Seção Retangular 20 X 50
V4 | 2º PAV. | 14 | 50 | 0 | 0.22 % | Contato com solo | 0 | Viga C-30 - Seção Retangular 14 X 50
V40 | 2º PAV. | 14 | 50 | 0 | 0.22 % | Contato com solo | 0 | Viga C-30 - Seção Retangular 14 X 50
V41 | 2º PAV. | 14 | 50 | 0 | 0.22 % | Externo | 682.5 | Viga C-30 - Seção Retangular 14 X 50
V42 | 2º PAV. | 14 | 50 | 0 | 0.22 % | Externo | 682.5 | Viga C-30 - Seção Retangular 14 X 50
V43 | 2º PAV. | 14 | 50 | 0 | 0.53 % | Externo | 682.5 | Viga C-30 - Seção Retangular 14 X 50
2 x V44 | 2º PAV. | 14 | 50 | 0 | 0.34 % | Externo | 682.5 | Viga C-30 - Seção Retangular 14 X 50
V44 | 2º PAV. | 14 | 50 | 0 | 0.34 % | Externo | 0 | Viga C-30 - Seção Retangular 14 X 50
V45 | 2º PAV. | 14 | 50 | 0 | 0.22 % | Externo | 682.5 | Viga C-30 - Seção Retangular 14 X 50
V46 | 2º PAV. | 14 | 50 | 0 | 0.22 % | Externo | 682.5 | Viga C-30 - Seção Retangular 14 X 50
V47 | 2º PAV. | 14 | 50 | 0 | 0.22 % | Externo | 682.5 | Viga C-30 - Seção Retangular 14 X 50
4 x V48 | 2º PAV. | 14 | 50 | 0 | 0.53 % | Externo | 0 | Viga C-30 - Seção Retangular 14 X 50
6 x V49 | 2º PAV. | 14 | 50 | 0 | 0.70 % | Externo | 682.5 | Viga C-30 - Seção Retangular 14 X 50
V49 | 2º PAV. | 14 | 50 | 0 | 0.35 % | Externo | 682.5 | Viga C-30 - Seção Retangular 14 X 50
4 x V5 | 2º PAV. | 20 | 50 | 0 | 0.16 % | Externo | 682.5 | Viga C-30 - Seção Retangular 20 X 50
V5 | 2º PAV. | 20 | 50 | 0 | 0.16 % | Externo | 0 | Viga C-30 - Seção Retangular 20 X 50
5 x V50 | 2º PAV. | 14 | 50 | 0 | 0.22 % | Externo | 682.5 | Viga C-30 - Seção Retangular 14 X 50
2 x V50 | 2º PAV. | 14 | 50 | 0 | 0.34 % | Externo | 682.5 | Viga C-30 - Seção Retangular 14 X 50
3 x V51 | 2º PAV. | 14 | 50 | 0 | 0.22 % | Externo | 682.5 | Viga C-30 - Seção Retangular 14 X 50
V51 | 2º PAV. | 14 | 50 | 0 | 0.34 % | Externo | 682.5 | Viga C-30 - Seção Retangular 14 X 50
4 x V52 | 2º PAV. | 14 | 50 | 0 | 0.34 % | Externo | 682.5 | Viga C-30 - Seção Retangular 14 X 50
V52 | 2º PAV. | 14 | 50 | 0 | 0.22 % | Externo | 682.5 | Viga C-30 - Seção Retangular 14 X 50
V6 | 2º PAV. | 14 | 50 | 0 | 0.22 % | Externo | 682.5 | Viga C-30 - Seção Retangular 14 X 50
V7 | 2º PAV. | 14 | 50 | 0 | 0.22 % | Externo | 682.5 | Viga C-30 - Seção Retangular 14 X 50
V8 | 2º PAV. | 14 | 50 | 0 | 0.22 % | Externo | 682.5 | Viga C-30 - Seção Retangular 14 X 50
2 x V9 | 2º PAV. | 14 | 50 | 0 | 0.34 % | Contato com solo | 0 | Viga C-30 - Seção Retangular 14 X 50
2 x V1 | 3º PAV. | 20 | 40 | 0 | 0.46 % | Contato com solo | 0 | Viga C-30 - Seção Retangular 20 X 40
2 x V10 | 3º PAV. | 14 | 50 | 0 | 0.70 % | Externo | 682.5 | Viga C-30 - Seção Retangular 14 X 50
V11 | 3º PAV. | 14 | 50 | 0 | 0.34 % | Externo | 682.5 | Viga C-30 - Seção Retangular 14 X 50
V12 | 3º PAV. | 14 | 50 | 0 | 0.53 % | Externo | 0 | Viga C-30 - Seção Retangular 14 X 50
3 x V13 | 3º PAV. | 20 | 50 | 0 | 0.25 % | Externo | 682.5 | Viga C-30 - Seção Retangular 20 X 50
V14 | 3º PAV. | 14 | 50 | 0 | 0.22 % | Contato com solo | 0 | Viga C-30 - Seção Retangular 14 X 50
V15 | 3º PAV. | 14 | 50 | 0 | 0.22 % | Externo | 682.5 | Viga C-30 - Seção Retangular 14 X 50
V16 | 3º PAV. | 14 | 50 | 0 | 0.22 % | Externo | 682.5 | Viga C-30 - Seção Retangular 14 X 50
2 x V17 | 3º PAV. | 14 | 50 | 0 | 0.34 % | Externo | 0 | Viga C-30 - Seção Retangular 14 X 50
V17 | 3º PAV. | 14 | 50 | 0 | 0.34 % | Externo | 292.5 | Viga C-30 - Seção Retangular 14 X 50
V18 | 3º PAV. | 14 | 50 | 0 | 0.22 % | Externo | 682.5 | Viga C-30 - Seção Retangular 14 X 50
V19 | 3º PAV. | 14 | 50 | 0 | 0.22 % | Externo | 292.5 | Viga C-30 - Seção Retangular 14 X 50
V2 | 3º PAV. | 14 | 50 | 0 | 0.34 % | Externo | 682.5 | Viga C-30 - Seção Retangular 14 X 50
V2 | 3º PAV. | 14 | 50 | 0 | 0.22 % | Externo | 682.5 | Viga C-30 - Seção Retangular 14 X 50
V20 | 3º PAV. | 14 | 50 | 0 | 0.22 % | Externo | 682.5 | Viga C-30 - Seção Retangular 14 X 50
3 x V21 | 3º PAV. | 14 | 50 | 0 | 0.53 % | Externo | 0 | Viga C-30 - Seção Retangular 14 X 50
V21 | 3º PAV. | 14 | 50 | 0 | 0.53 % | Externo | 682.5 | Viga C-30 - Seção Retangular 14 X 50
V22 | 3º PAV. | 20 | 50 | 0 | 0.16 % | Externo | 292.5 | Viga C-30 - Seção Retangular 20 X 50
V22 | 3º PAV. | 20 | 50 | 0 | 0.31 % | Externo | 292.5 | Viga C-30 - Seção Retangular 20 X 50
4 x V23 | 3º PAV. | 14 | 50 | 0 | 0.22 % | Externo | 682.5 | Viga C-30 - Seção Retangular 14 X 50
2 x V23 | 3º PAV. | 14 | 50 | 0 | 0.53 % | Externo | 682.5 | Viga C-30 - Seção Retangular 14 X 50
V23 | 3º PAV. | 14 | 50 | 0 | 0.35 % | Externo | 682.5 | Viga C-30 - Seção Retangular 14 X 50
3 x V24 | 3º PAV. | 14 | 50 | 0 | 0.45 % | Externo | 682.5 | Viga C-30 - Seção Retangular 14 X 50
V24 | 3º PAV. | 14 | 50 | 0 | 0.22 % | Externo | 292.5 | Viga C-30 - Seção Retangular 14 X 50
V24 | 3º PAV. | 14 | 50 | 0 | 0.22 % | Externo | 682.5 | Viga C-30 - Seção Retangular 14 X 50
7 x V25 | 3º PAV. | 14 | 50 | 0 | 0.22 % | Externo | 292.5 | Viga C-30 - Seção Retangular 14 X 50
V3 | 3º PAV. | 14 | 50 | 0 | 0.35 % | Externo | 682.5 | Viga C-30 - Seção Retangular 14 X 50
2 x V3 | 3º PAV. | 14 | 50 | 0 | 0.53 % | Externo | 682.5 | Viga C-30 - Seção Retangular 14 X 50
V4 | 3º PAV. | 14 | 50 | 0 | 0.22 % | Contato com solo | 0 | Viga C-30 - Seção Retangular 14 X 50
2 x V5 | 3º PAV. | 20 | 50 | 0 | 0.16 % | Externo | 682.5 | Viga C-30 - Seção Retangular 20 X 50
3 x V5 | 3º PAV. | 20 | 50 | 0 | 0.31 % | Externo | 682.5 | Viga C-30 - Seção Retangular 20 X 50
3 x V6 | 3º PAV. | 20 | 50 | 0 | 0.25 % | Externo | 0 | Viga C-30 - Seção Retangular 20 X 50
V6 | 3º PAV. | 20 | 50 | 0 | 0.37 % | Externo | 0 | Viga C-30 - Seção Retangular 20 X 50
V7 | 3º PAV. | 14 | 50 | 0 | 0.22 % | Externo | 292.5 | Viga C-30 - Seção Retangular 14 X 50
V7 | 3º PAV. | 14 | 50 | 0 | 0.22 % | Externo | 0 | Viga C-30 - Seção Retangular 14 X 50
2 x V8 | 3º PAV. | 20 | 50 | 0 | 0.80 % | Externo | 682.5 | Viga C-30 - Seção Retangular 20 X 50
2 x V9 | 3º PAV. | 20 | 50 | 0 | 1.21 % | Externo | 0 | Viga C-30 - Seção Retangular 20 X 50
3 x V1 | COBERTURA | 14 | 40 | 0 | 0.28 % | Externo | 292.5 | Viga C-30 - Seção Retangular 14 X 40
V2 | COBERTURA | 14 | 30 | 0 | 0.37 % | Contato com solo | 585 | Viga C-30 - Seção Retangular 14 X 30
V3 | COBERTURA | 14 | 30 | 0 | 0.37 % | Contato com solo | 585 | Viga C-30 - Seção Retangular 14 X 30
V4 | COBERTURA | 14 | 30 | 0 | 0.37 % | Contato com solo | 585 | Viga C-30 - Seção Retangular 14 X 30
2 x V5 | COBERTURA | 14 | 30 | 0 | 0.37 % | Contato com solo | 585 | Viga C-30 - Seção Retangular 14 X 30
2 x V1 | COBERTURA | 14 | 40 | 0 | 1.31 % | Externo | 292.5 | Viga C-30 - Seção Retangular 14 X 40
2 x V10 | COBERTURA | 14 | 40 | 0 | 0.28 % | Externo | 292.5 | Viga C-30 - Seção Retangular 14 X 40
V11 | COBERTURA | 14 | 40 | 0 | 0.28 % | Externo | 292.5 | Viga C-30 - Seção Retangular 14 X 40
2 x V2 | COBERTURA | 14 | 40 | 0 | 0.28 % | Externo | 292.5 | Viga C-30 - Seção Retangular 14 X 40
V3 | COBERTURA | 14 | 40 | 0 | 0.28 % | Externo | 292.5 | Viga C-30 - Seção Retangular 14 X 40
V4 | COBERTURA | 14 | 40 | 0 | 0.28 % | Externo | 292.5 | Viga C-30 - Seção Retangular 14 X 40
V5 | COBERTURA | 14 | 40 | 0 | 0.28 % | Externo | 292.5 | Viga C-30 - Seção Retangular 14 X 40
V6 | COBERTURA | 14 | 40 | 0 | 0.28 % | Externo | 292.5 | Viga C-30 - Seção Retangular 14 X 40
V7 | COBERTURA | 14 | 40 | 0 | 0.28 % | Externo | 292.5 | Viga C-30 - Seção Retangular 14 X 40
V8 | COBERTURA | 14 | 40 | 0 | 0.28 % | Externo | 292.5 | Viga C-30 - Seção Retangular 14 X 40
4 x V9 | COBERTURA | 14 | 40 | 0 | 0.28 % | Externo | 292.5 | Viga C-30 - Seção Retangular 14 X 40

# IfcColumn (198)
Material: Concreto
Pset_ConcreteElementGeneral - ConstructionMethod: InSitu; ExposureClass: 2; StrengthClass: C-30
AltoQi_Eberick_Elemento - Elemento: Pilar; Tipo: retangular
AltoQi_Eberick_Padrão - Classe de concreto: C-30
Pset_ColumnCommon - IsExternal: yes; LoadBearing: yes
Name | In | ConcreteCover (cm) = Cobrimento (cm) | Seção_b (cm) | Seção_h (cm) | Elevação (cm) | Taxa de armadura | Taxa de compressão bruta | Taxa de compressão homogeneizada | Ambiente | Reference
P.A1 | PÁTIO | 2.5 | 70 | 70 | 0 | 0.66 % | 0.08 | 0.07 | Externo | Pilar C-30 - Retangular 70x70
P.A10 | PÁTIO | 2.5 | 60 | 70 | 0 | 0.77 % | 0.19 | 0.17 | Externo | Pilar C-30 - Retangular 60x70
P.A11 | PÁTIO | 2.5 | 60 | 70 | 0 | 0.77 % | 0.11 | 0.1 | Externo | Pilar C-30 - Retangular 60x70
P.A12 | PÁTIO | 2.5 | 60 | 70 | 0 | 0.77 % | 0.12 | 0.11 | Externo | Pilar C-30 - Retangular 60x70
P.A13 | PÁTIO | 2.5 | 70 | 70 | 0 | 0.66 % | 0.09 | 0.08 | Externo | Pilar C-30 - Retangular 70x70
P.A14 | PÁTIO | 2.5 | 70 | 70 | 0 | 0.66 % | 0.13 | 0.12 | Externo | Pilar C-30 - Retangular 70x70
P.A15 | PÁTIO | 2.5 | 50 | 50 | 0 | 0.97 % | 0.18 | 0.16 | Externo | Pilar C-30 - Retangular 50x50
P.A16 | PÁTIO | 2.5 | 70 | 70 | 0 | 0.51 % | 0.1 | 0.09 | Externo | Pilar C-30 - Retangular 70x70
P.A17 | PÁTIO | 2.5 | 60 | 70 | 0 | 0.77 % | 0.08 | 0.08 | Externo | Pilar C-30 - Retangular 60x70
P.A2 | PÁTIO | 2.5 | 60 | 70 | 0 | 0.77 % | 0.13 | 0.12 | Externo | Pilar C-30 - Retangular 60x70
P.A3 | PÁTIO | 2.5 | 60 | 70 | 0 | 0.77 % | 0.12 | 0.11 | Externo | Pilar C-30 - Retangular 60x70
P.A4 | PÁTIO | 2.5 | 60 | 70 | 0 | 0.77 % | 0.12 | 0.11 | Externo | Pilar C-30 - Retangular 60x70
P.A5 | PÁTIO | 2.5 | 40 | 40 | 0 | 1.51 % | 0.15 | 0.12 | Externo | Pilar C-30 - Retangular 40x40
P.A6 | PÁTIO | 2.5 | 60 | 70 | 0 | 0.77 % | 0.1 | 0.09 | Externo | Pilar C-30 - Retangular 60x70
P.A7 | PÁTIO | 2.5 | 60 | 70 | 0 | 0.77 % | 0.14 | 0.13 | Externo | Pilar C-30 - Retangular 60x70
P.A8 | PÁTIO | 2.5 | 60 | 70 | 0 | 0.77 % | 0.13 | 0.12 | Externo | Pilar C-30 - Retangular 60x70
P.A9 | PÁTIO | 2.5 | 60 | 70 | 0 | 0.77 % | 0.05 | 0.05 | Externo | Pilar C-30 - Retangular 60x70
P.MURO1 | PÁTIO | 4 | 30 | 50 | 0 | 1.88 % | 0.05 | 0.04 | Contato com solo | Pilar C-30 - Retangular 30x50
P.MURO2 | PÁTIO | 4 | 30 | 30 | 0 | 2.68 % | 0.17 | 0.13 | Contato com solo | Pilar C-30 - Retangular 30x30
P.MURO5 | PÁTIO | 4 | 30 | 30 | 0 | 2.68 % | 0.15 | 0.11 | Contato com solo | Pilar C-30 - Retangular 30x30
P10 | PÁTIO | 2.5 | 30 | 40 | 0 | 2.01 % | 0.43 | 0.34 | Externo | Pilar C-30 - Retangular 30x40
P11 | PÁTIO | 2.5 | 30 | 40 | 0 | 1.34 % | 0.53 | 0.44 | Externo | Pilar C-30 - Retangular 30x40
P12 | PÁTIO | 2.5 | 30 | 40 | 0 | 1.68 % | 0.41 | 0.33 | Externo | Pilar C-30 - Retangular 30x40
P14 | PÁTIO | 2.5 | 30 | 50 | 0 | 2.68 % | 0.45 | 0.34 | Externo | Pilar C-30 - Retangular 30x50
P15 | PÁTIO | 2.5 | 30 | 40 | 0 | 1.02 % | 0.46 | 0.4 | Externo | Pilar C-30 - Retangular 30x40
P18 | PÁTIO | 2.5 | 30 | 40 | 0 | 1.68 % | 0.41 | 0.33 | Externo | Pilar C-30 - Retangular 30x40
P19 | PÁTIO | 2.5 | 30 | 50 | 0 | 0.42 % | 0.17 | 0.16 | Externo | Pilar C-30 - Retangular 30x50
P20 | PÁTIO | 2.5 | 30 | 50 | 0 | 1.61 % | 0.27 | 0.22 | Externo | Pilar C-30 - Retangular 30x50
P21 | PÁTIO | 2.5 | 30 | 50 | 0 | 2.41 % | 0.38 | 0.3 | Externo | Pilar C-30 - Retangular 30x50
P22 | PÁTIO | 2.5 | 30 | 40 | 0 | 1.23 % | 0.4 | 0.35 | Externo | Pilar C-30 - Retangular 30x40
P23 | PÁTIO | 2.5 | 30 | 40 | 0 | 0.67 % | 0.55 | 0.49 | Externo | Pilar C-30 - Retangular 30x40
P24 | PÁTIO | 2.5 | 40 | 40 | 0 | 1.01 % | 0.37 | 0.32 | Externo | Pilar C-30 - Retangular 40x40
P25 | PÁTIO | 2.5 | 50 | 50 | 0 | 0.64 % | 0.28 | 0.25 | Externo | Pilar C-30 - Retangular 50x50
P26 | PÁTIO | 2.5 | 30 | 50 | 0 | 1.61 % | 0.33 | 0.28 | Externo | Pilar C-30 - Retangular 30x50
P27 | PÁTIO | 2.5 | 20 | 40 | 0 | 2.51 % | 0.47 | 0.35 | Externo | Pilar C-30 - Retangular 20x40
P.MURO1 | TÉRREO | 2.5 | 30 | 50 | 0 | 1.88 % | 0.03 | 0.02 | Externo | Pilar C-30 - Retangular 30x50
P.MURO2 | TÉRREO | 2.5 | 30 | 30 | 0 | 2.68 % | 0.05 | 0.04 | Externo | Pilar C-30 - Retangular 30x30
P.MURO3 | TÉRREO | 2.5 | 25 | 45 | 0 | 0.42 % | 0.05 | 0.05 | Externo | Pilar C-30 - Retangular 25x45
P.MURO4 | TÉRREO | 2.5 | 25 | 45 | 0 | 0.71 % | 0.03 | 0.03 | Externo | Pilar C-30 - Retangular 25x45
P.MURO5 | TÉRREO | 2.5 | 30 | 30 | 0 | 2.68 % | 0.05 | 0.04 | Externo | Pilar C-30 - Retangular 30x30
P.RAMPA1 | TÉRREO | 2.5 | 20 | 20 | 0 | 0.79 % | 0.03 | 0.03 | Externo | Pilar C-30 - Retangular 20x20
P.RAMPA2 | TÉRREO | 2.5 | 20 | 20 | 0 | 3.68 % | 0.01 | 0.01 | Externo | Pilar C-30 - Retangular 20x20
P.RAMPA3 | TÉRREO | 2.5 | 20 | 30 | 0 | 2.68 % | 0.03 | 0.02 | Externo | Pilar C-30 - Retangular 20x30
P.RAMPA4 | TÉRREO | 2.5 | 20 | 20 | 0 | 3.68 % | 0.01 | 0.01 | Externo | Pilar C-30 - Retangular 20x20
P.RAMPA5 | TÉRREO | 2.5 | 20 | 30 | 0 | 1.23 % | 0.12 | 0.1 | Externo | Pilar C-30 - Retangular 20x30
P1 | TÉRREO | 2.5 | 40 | 50 | 0 | 2.01 % | 0.12 | 0.1 | Externo | Pilar C-30 - Retangular 40x50
P10 | TÉRREO | 2.5 | 30 | 40 | 0 | 2.01 % | 0.38 | 0.3 | Externo | Pilar C-30 - Retangular 30x40
P11 | TÉRREO | 2.5 | 30 | 40 | 0 | 1.34 % | 0.47 | 0.39 | Externo | Pilar C-30 - Retangular 30x40
P12 | TÉRREO | 2.5 | 30 | 40 | 0 | 1.34 % | 0.38 | 0.32 | Externo | Pilar C-30 - Retangular 30x40
P13 | TÉRREO | 2.5 | 20 | 40 | 0 | 1.23 % | 0.1 | 0.09 | Externo | Pilar C-30 - Retangular 20x40
P14 | TÉRREO | 2.5 | 30 | 50 | 0 | 0.42 % | 0.26 | 0.25 | Externo | Pilar C-30 - Retangular 30x50
P15 | TÉRREO | 2.5 | 30 | 40 | 0 | 1.02 % | 0.39 | 0.34 | Externo | Pilar C-30 - Retangular 30x40
P16 | TÉRREO | 2.5 | 30 | 40 | 0 | 1.68 % | 0.14 | 0.12 | Externo | Pilar C-30 - Retangular 30x40
P17 | TÉRREO | 2.5 | 20 | 20 | 0 | 2.45 % | 0.02 | 0.02 | Externo | Pilar C-30 - Retangular 20x20
P18 | TÉRREO | 2.5 | 30 | 40 | 0 | 1.34 % | 0.34 | 0.29 | Externo | Pilar C-30 - Retangular 30x40
P19 | TÉRREO | 2.5 | 30 | 50 | 0 | 0.42 % | 0.15 | 0.14 | Externo | Pilar C-30 - Retangular 30x50
P2 | TÉRREO | 2.5 | 30 | 40 | 0 | 2.35 % | 0.32 | 0.25 | Externo | Pilar C-30 - Retangular 30x40
P20 | TÉRREO | 2.5 | 20 | 50 | 0 | 2.41 % | 0.32 | 0.25 | Externo | Pilar C-30 - Retangular 20x50
P21 | TÉRREO | 2.5 | 30 | 50 | -1.45 | 2.41 % | 0.25 | 0.2 | Externo | Pilar C-30 - Retangular 30x50
P22 | TÉRREO | 2.5 | 30 | 40 | 0 | 1.23 % | 0.41 | 0.35 | Externo | Pilar C-30 - Retangular 30x40
P23 | TÉRREO | 2.5 | 30 | 40 | 0 | 2.35 % | 0.51 | 0.39 | Externo | Pilar C-30 - Retangular 30x40
P24 | TÉRREO | 2.5 | 30 | 40 | 0 | 2.68 % | 0.51 | 0.39 | Externo | Pilar C-30 - Retangular 30x40
P25 | TÉRREO | 2.5 | 30 | 40 | 0 | 3.02 % | 0.6 | 0.45 | Externo | Pilar C-30 - Retangular 30x40
P26 | TÉRREO | 2.5 | 30 | 50 | 0 | 1.61 % | 0.34 | 0.28 | Externo | Pilar C-30 - Retangular 30x50
P27 | TÉRREO | 2.5 | 20 | 40 | 0 | 2.51 % | 0.41 | 0.31 | Externo | Pilar C-30 - Retangular 20x40
P28 | TÉRREO | 2.5 | 30 | 50 | 0 | 0.80 % | 0.28 | 0.25 | Externo | Pilar C-30 - Retangular 30x50
P29 | TÉRREO | 2.5 | 30 | 40 | 0 | 1.34 % | 0.35 | 0.29 | Externo | Pilar C-30 - Retangular 30x40
P3 | TÉRREO | 2.5 | 30 | 40 | 0 | 2.01 % | 0.31 | 0.24 | Externo | Pilar C-30 - Retangular 30x40
P30 | TÉRREO | 2.5 | 30 | 40 | 0 | 0.67 % | 0.33 | 0.3 | Externo | Pilar C-30 - Retangular 30x40
P31 | TÉRREO | 2.5 | 30 | 40 | 0 | 2.68 % | 0.27 | 0.21 | Externo | Pilar C-30 - Retangular 30x40
P32 | TÉRREO | 2.5 | 30 | 50 | 0 | 1.07 % | 0.21 | 0.19 | Externo | Pilar C-30 - Retangular 30x50
P33 | TÉRREO | 2.5 | 20 | 50 | 0 | 0.63 % | 0.21 | 0.2 | Externo | Pilar C-30 - Retangular 20x50
P34 | TÉRREO | 2.5 | 30 | 40 | 0 | 1.02 % | 0.28 | 0.24 | Externo | Pilar C-30 - Retangular 30x40
P35 | TÉRREO | 2.5 | 30 | 40 | 0 | 0.82 % | 0.33 | 0.29 | Externo | Pilar C-30 - Retangular 30x40
P36 | TÉRREO | 2.5 | 30 | 40 | 0 | 1.02 % | 0.24 | 0.21 | Externo | Pilar C-30 - Retangular 30x40
P4 | TÉRREO | 2.5 | 30 | 40 | 0 | 2.35 % | 0.26 | 0.21 | Externo | Pilar C-30 - Retangular 30x40
P5 | TÉRREO | 2.5 | 20 | 40 | 0 | 0.79 % | 0.17 | 0.15 | Externo | Pilar C-30 - Retangular 20x40
P6 | TÉRREO | 2.5 | 20 | 40 | 0 | 1.23 % | 0.08 | 0.07 | Externo | Pilar C-30 - Retangular 20x40
P7 | TÉRREO | 2.5 | 30 | 40 | 0 | 0.52 % | 0.25 | 0.23 | Externo | Pilar C-30 - Retangular 30x40
P8 | TÉRREO | 2.5 | 30 | 50 | 0 | 2.14 % | 0.31 | 0.25 | Externo | Pilar C-30 - Retangular 30x50
P9 | TÉRREO | 2.5 | 40 | 40 | 0 | 2.51 % | 0.29 | 0.22 | Externo | Pilar C-30 - Retangular 40x40
P.MURO1 | 1º PAV. | 2.5 | 20 | 50 | -100 | 0.47 % | 0.01 | 0.01 | Externo | Pilar C-30 - Retangular 20x50
P.MURO2 | 1º PAV. | 2.5 | 14 | 30 | -100 | 1.75 % | 0.01 | 0.01 | Externo | Pilar C-30 - Retangular 14x30
P.MURO3 | 1º PAV. | 2.5 | 25 | 45 | -40 | 0.42 % | 0.02 | 0.02 | Externo | Pilar C-30 - Retangular 25x45
P.MURO4 | 1º PAV. | 2.5 | 25 | 45 | -40 | 0.42 % | 0.01 | 0.01 | Externo | Pilar C-30 - Retangular 25x45
P1 | 1º PAV. | 2.5 | 20 | 40 | 0 | 3.02 % | 0.24 | 0.17 | Externo | Pilar C-30 - Retangular 20x40
P10 | 1º PAV. | 2.5 | 20 | 40 | 0 | 3.02 % | 0.43 | 0.31 | Externo | Pilar C-30 - Retangular 20x40
P11 | 1º PAV. | 2.5 | 20 | 40 | 0 | 1.51 % | 0.49 | 0.4 | Externo | Pilar C-30 - Retangular 20x40
P12 | 1º PAV. | 2.5 | 20 | 40 | 0 | 1.23 % | 0.41 | 0.35 | Externo | Pilar C-30 - Retangular 20x40
P13 | 1º PAV. | 2.5 | 20 | 40 | 0 | 1.23 % | 0.07 | 0.06 | Externo | Pilar C-30 - Retangular 20x40
P14 | 1º PAV. | 2.5 | 20 | 40 | 0 | 0.59 % | 0.33 | 0.3 | Externo | Pilar C-30 - Retangular 20x40
P15 | 1º PAV. | 2.5 | 20 | 40 | 0 | 1.53 % | 0.42 | 0.35 | Externo | Pilar C-30 - Retangular 20x40
P16 | 1º PAV. | 2.5 | 20 | 40 | 0 | 0.59 % | 0.15 | 0.14 | Externo | Pilar C-30 - Retangular 20x40
P18 | 1º PAV. | 2.5 | 20 | 40 | 0 | 2.01 % | 0.3 | 0.23 | Externo | Pilar C-30 - Retangular 20x40
P19 | 1º PAV. | 2.5 | 20 | 40 | 0 | 0.79 % | 0.17 | 0.16 | Externo | Pilar C-30 - Retangular 20x40
P2 | 1º PAV. | 2.5 | 20 | 40 | 0 | 3.52 % | 0.3 | 0.21 | Externo | Pilar C-30 - Retangular 20x40
P20 | 1º PAV. | 2.5 | 20 | 40 | 0 | 0.92 % | 0.27 | 0.24 | Externo | Pilar C-30 - Retangular 20x40
P21 | 1º PAV. | 2.5 | 20 | 50 | 0 | 3.22 % | 0.38 | 0.27 | Externo | Pilar C-30 - Retangular 20x50
P22 | 1º PAV. | 2.5 | 20 | 40 | 0 | 1.84 % | 0.36 | 0.3 | Externo | Pilar C-30 - Retangular 20x40
P23 | 1º PAV. | 2.5 | 20 | 40 | 0 | 1.51 % | 0.48 | 0.39 | Externo | Pilar C-30 - Retangular 20x40
P24 | 1º PAV. | 2.5 | 20 | 40 | 0 | 3.52 % | 0.56 | 0.4 | Externo | Pilar C-30 - Retangular 20x40
P25 | 1º PAV. | 2.5 | 20 | 40 | 0 | 3.02 % | 0.64 | 0.47 | Externo | Pilar C-30 - Retangular 20x40
P26 | 1º PAV. | 2.5 | 20 | 50 | 0 | 2.01 % | 0.37 | 0.29 | Externo | Pilar C-30 - Retangular 20x50
P27 | 1º PAV. | 2.5 | 20 | 40 | 0 | 0.59 % | 0.21 | 0.19 | Externo | Pilar C-30 - Retangular 20x40
P28 | 1º PAV. | 2.5 | 20 | 50 | 0 | 3.22 % | 0.4 | 0.29 | Externo | Pilar C-30 - Retangular 20x50
P29 | 1º PAV. | 2.5 | 20 | 40 | 0 | 2.01 % | 0.34 | 0.26 | Externo | Pilar C-30 - Retangular 20x40
P3 | 1º PAV. | 2.5 | 20 | 40 | 0 | 2.01 % | 0.34 | 0.26 | Externo | Pilar C-30 - Retangular 20x40
P30 | 1º PAV. | 2.5 | 20 | 40 | 0 | 2.01 % | 0.38 | 0.29 | Externo | Pilar C-30 - Retangular 20x40
P31 | 1º PAV. | 2.5 | 30 | 40 | 0 | 2.68 % | 0.17 | 0.13 | Externo | Pilar C-30 - Retangular 30x40
P32 | 1º PAV. | 2.5 | 20 | 40 | 0 | 1.23 % | 0.19 | 0.16 | Externo | Pilar C-30 - Retangular 20x40
P33 | 1º PAV. | 2.5 | 20 | 40 | 0 | 0.79 % | 0.19 | 0.17 | Externo | Pilar C-30 - Retangular 20x40
P34 | 1º PAV. | 2.5 | 20 | 40 | 0 | 0.59 % | 0.3 | 0.28 | Externo | Pilar C-30 - Retangular 20x40
P35 | 1º PAV. | 2.5 | 20 | 40 | 0 | 0.92 % | 0.35 | 0.3 | Externo | Pilar C-30 - Retangular 20x40
P36 | 1º PAV. | 2.5 | 20 | 40 | 0 | 1.53 % | 0.25 | 0.21 | Externo | Pilar C-30 - Retangular 20x40
P4 | 1º PAV. | 2.5 | 20 | 40 | 0 | 1.23 % | 0.3 | 0.25 | Externo | Pilar C-30 - Retangular 20x40
P5 | 1º PAV. | 2.5 | 20 | 40 | 0 | 0.59 % | 0.1 | 0.09 | Externo | Pilar C-30 - Retangular 20x40
P6 | 1º PAV. | 2.5 | 20 | 40 | 0 | 1.23 % | 0.1 | 0.09 | Externo | Pilar C-30 - Retangular 20x40
P7 | 1º PAV. | 2.5 | 20 | 40 | 0 | 0.59 % | 0.28 | 0.26 | Externo | Pilar C-30 - Retangular 20x40
P8 | 1º PAV. | 2.5 | 20 | 50 | 0 | 3.22 % | 0.41 | 0.3 | Externo | Pilar C-30 - Retangular 20x50
P9 | 1º PAV. | 2.5 | 20 | 40 | 0 | 1.53 % | 0.43 | 0.36 | Externo | Pilar C-30 - Retangular 20x40
P1 | 2º PAV. | 2.5 | 20 | 40 | 0 | 3.02 % | 0.16 | 0.12 | Externo | Pilar C-30 - Retangular 20x40
P10 | 2º PAV. | 2.5 | 20 | 40 | 0 | 3.02 % | 0.31 | 0.23 | Externo | Pilar C-30 - Retangular 20x40
P11 | 2º PAV. | 2.5 | 20 | 40 | 0 | Não calculado | Não calculado | Não calculado | Externo | Pilar C-30 - Retangular 20x40
P12 | 2º PAV. | 2.5 | 20 | 40 | 0 | 1.23 % | 0.25 | 0.21 | Externo | Pilar C-30 - Retangular 20x40
P13 | 2º PAV. | 2.5 | 20 | 40 | 0 | 1.23 % | 0.06 | 0.05 | Externo | Pilar C-30 - Retangular 20x40
P14 | 2º PAV. | 2.5 | 20 | 40 | 0 | 0.59 % | 0.22 | 0.2 | Externo | Pilar C-30 - Retangular 20x40
P15 | 2º PAV. | 2.5 | 20 | 40 | 0 | 1.53 % | 0.29 | 0.24 | Externo | Pilar C-30 - Retangular 20x40
P16 | 2º PAV. | 2.5 | 20 | 40 | 0 | 0.59 % | 0.1 | 0.09 | Externo | Pilar C-30 - Retangular 20x40
P18 | 2º PAV. | 2.5 | 20 | 40 | 0 | 2.01 % | 0.15 | 0.11 | Externo | Pilar C-30 - Retangular 20x40
P19 | 2º PAV. | 2.5 | 20 | 40 | 0 | 0.79 % | 0.08 | 0.07 | Externo | Pilar C-30 - Retangular 20x40
P2 | 2º PAV. | 2.5 | 20 | 40 | 0 | 3.52 % | 0.21 | 0.15 | Externo | Pilar C-30 - Retangular 20x40
P20 | 2º PAV. | 2.5 | 20 | 40 | 0 | 0.92 % | 0.17 | 0.15 | Externo | Pilar C-30 - Retangular 20x40
P22 | 2º PAV. | 2.5 | 20 | 40 | 0 | 1.84 % | 0.16 | 0.13 | Externo | Pilar C-30 - Retangular 20x40
P23 | 2º PAV. | 2.5 | 20 | 40 | 0 | 0.92 % | 0.24 | 0.21 | Externo | Pilar C-30 - Retangular 20x40
P24 | 2º PAV. | 2.5 | 20 | 40 | 0 | 0.79 % | 0.36 | 0.32 | Externo | Pilar C-30 - Retangular 20x40
P25 | 2º PAV. | 2.5 | 20 | 40 | 0 | 1.23 % | 0.39 | 0.33 | Externo | Pilar C-30 - Retangular 20x40
P26 | 2º PAV. | 2.5 | 20 | 40 | 0 | 2.01 % | 0.3 | 0.24 | Externo | Pilar C-30 - Retangular 20x40
P27 | 2º PAV. | 2.5 | 20 | 40 | 0 | 0.59 % | 0.1 | 0.09 | Externo | Pilar C-30 - Retangular 20x40
P28 | 2º PAV. | 2.5 | 20 | 50 | 0 | 1.61 % | 0.16 | 0.13 | Externo | Pilar C-30 - Retangular 20x50
P29 | 2º PAV. | 2.5 | 20 | 40 | 0 | 2.01 % | 0.23 | 0.18 | Externo | Pilar C-30 - Retangular 20x40
P3 | 2º PAV. | 2.5 | 20 | 40 | 0 | 2.01 % | 0.23 | 0.18 | Externo | Pilar C-30 - Retangular 20x40
P30 | 2º PAV. | 2.5 | 20 | 40 | 0 | 2.01 % | 0.25 | 0.2 | Externo | Pilar C-30 - Retangular 20x40
P31 | 2º PAV. | 2.5 | 30 | 40 | 0 | 2.68 % | 0.12 | 0.09 | Externo | Pilar C-30 - Retangular 30x40
P32 | 2º PAV. | 2.5 | 20 | 40 | 0 | 1.23 % | 0.13 | 0.11 | Externo | Pilar C-30 - Retangular 20x40
P33 | 2º PAV. | 2.5 | 20 | 40 | 0 | 0.79 % | 0.13 | 0.11 | Externo | Pilar C-30 - Retangular 20x40
P34 | 2º PAV. | 2.5 | 20 | 40 | 0 | 0.59 % | 0.19 | 0.18 | Externo | Pilar C-30 - Retangular 20x40
P35 | 2º PAV. | 2.5 | 20 | 40 | 0 | 0.92 % | 0.21 | 0.19 | Externo | Pilar C-30 - Retangular 20x40
P36 | 2º PAV. | 2.5 | 20 | 40 | 0 | 1.53 % | 0.16 | 0.13 | Externo | Pilar C-30 - Retangular 20x40
P37 | 2º PAV. | 2.5 | 20 | 30 | 0 | 3.35 % | 0 | 0 | Externo | Pilar C-30 - Retangular 20x30
P38 | 2º PAV. | 2.5 | 20 | 30 | 0 | 1.64 % | 0.01 | 0.01 | Externo | Pilar C-30 - Retangular 20x30
P39 | 2º PAV. | 2.5 | 20 | 30 | 0 | 1.64 % | 0.27 | 0.22 | Externo | Pilar C-30 - Retangular 20x30
P4 | 2º PAV. | 2.5 | 20 | 40 | 0 | 1.23 % | 0.2 | 0.17 | Externo | Pilar C-30 - Retangular 20x40
P40 | 2º PAV. | 2.5 | 20 | 30 | 0 | 3.35 % | 0 | 0 | Externo | Pilar C-30 - Retangular 20x30
P5 | 2º PAV. | 2.5 | 20 | 40 | 0 | 0.59 % | 0.07 | 0.06 | Externo | Pilar C-30 - Retangular 20x40
P6 | 2º PAV. | 2.5 | 20 | 40 | 0 | 1.23 % | 0.1 | 0.09 | Externo | Pilar C-30 - Retangular 20x40
P7 | 2º PAV. | 2.5 | 20 | 40 | 0 | 0.59 % | 0.18 | 0.16 | Externo | Pilar C-30 - Retangular 20x40
P8 | 2º PAV. | 2.5 | 20 | 50 | 0 | 3.22 % | 0.17 | 0.12 | Externo | Pilar C-30 - Retangular 20x50
P9 | 2º PAV. | 2.5 | 20 | 40 | 0 | 1.53 % | 0.29 | 0.24 | Externo | Pilar C-30 - Retangular 20x40
P1 | 3º PAV. | 2.5 | 20 | 40 | 0 | 3.02 % | 0.09 | 0.06 | Externo | Pilar C-30 - Retangular 20x40
P11 | 3º PAV. | 2.5 | 20 | 30 | 0 | 2.01 % | 0.21 | 0.16 | Externo | Pilar C-30 - Retangular 20x30
P12 | 3º PAV. | 2.5 | 20 | 40 | 0 | 1.23 % | 0.11 | 0.09 | Externo | Pilar C-30 - Retangular 20x40
P13 | 3º PAV. | 2.5 | 20 | 40 | 0 | 0.59 % | 0.04 | 0.04 | Externo | Pilar C-30 - Retangular 20x40
P14 | 3º PAV. | 2.5 | 20 | 40 | 0 | 0.59 % | 0.12 | 0.11 | Externo | Pilar C-30 - Retangular 20x40
P15 | 3º PAV. | 2.5 | 20 | 40 | 0 | 1.53 % | 0.18 | 0.15 | Externo | Pilar C-30 - Retangular 20x40
P16 | 3º PAV. | 2.5 | 20 | 40 | 0 | 0.59 % | 0.05 | 0.04 | Externo | Pilar C-30 - Retangular 20x40
P2 | 3º PAV. | 2.5 | 20 | 40 | 0 | 3.02 % | 0.1 | 0.07 | Externo | Pilar C-30 - Retangular 20x40
P20 | 3º PAV. | 2.5 | 20 | 40 | 0 | 0.92 % | 0.1 | 0.09 | Externo | Pilar C-30 - Retangular 20x40
P24 | 3º PAV. | 2.5 | 20 | 40 | 0 | 0.79 % | 0.16 | 0.15 | Externo | Pilar C-30 - Retangular 20x40
P25 | 3º PAV. | 2.5 | 20 | 40 | 0 | 0.92 % | 0.18 | 0.15 | Externo | Pilar C-30 - Retangular 20x40
P26 | 3º PAV. | 2.5 | 20 | 40 | 0 | 2.01 % | 0.15 | 0.11 | Externo | Pilar C-30 - Retangular 20x40
P3 | 3º PAV. | 2.5 | 20 | 40 | 0 | 2.01 % | 0.13 | 0.1 | Externo | Pilar C-30 - Retangular 20x40
P33 | 3º PAV. | 2.5 | 20 | 40 | 0 | 0.79 % | 0.06 | 0.05 | Externo | Pilar C-30 - Retangular 20x40
P34 | 3º PAV. | 2.5 | 20 | 40 | 0 | 0.59 % | 0.08 | 0.07 | Externo | Pilar C-30 - Retangular 20x40
P35 | 3º PAV. | 2.5 | 20 | 40 | 0 | 0.92 % | 0.09 | 0.08 | Externo | Pilar C-30 - Retangular 20x40
P36 | 3º PAV. | 2.5 | 20 | 40 | 0 | 0.92 % | 0.07 | 0.06 | Externo | Pilar C-30 - Retangular 20x40
P4 | 3º PAV. | 2.5 | 20 | 40 | 0 | 0.79 % | 0.11 | 0.1 | Externo | Pilar C-30 - Retangular 20x40
P41 | 3º PAV. | 2.5 | 20 | 40 | 0 | 3.52 % | 0.22 | 0.16 | Externo | Pilar C-30 - Retangular 20x40
P5 | 3º PAV. | 2.5 | 20 | 40 | 0 | 0.59 % | 0.05 | 0.04 | Externo | Pilar C-30 - Retangular 20x40
P6 | 3º PAV. | 2.5 | 20 | 40 | 0 | 1.23 % | 0.09 | 0.08 | Externo | Pilar C-30 - Retangular 20x40
P7 | 3º PAV. | 2.5 | 20 | 40 | 0 | 0.59 % | 0.09 | 0.08 | Externo | Pilar C-30 - Retangular 20x40
P9 | 3º PAV. | 2.5 | 20 | 40 | 0 | 1.53 % | 0.15 | 0.13 | Externo | Pilar C-30 - Retangular 20x40
P1 | COBERTURA | 2.5 | 14 | 30 | 0 | 2.87 % | 0.03 | 0.02 | Externo | Pilar C-30 - Retangular 14x30
P11 | COBERTURA | 2.5 | 20 | 30 | 0 | 2.01 % | 0.06 | 0.05 | Externo | Pilar C-30 - Retangular 20x30
P12 | COBERTURA | 2.5 | 14 | 30 | 0 | 0.75 % | 0.04 | 0.03 | Externo | Pilar C-30 - Retangular 14x30
P13 | COBERTURA | 2.5 | 20 | 40 | 0 | 0.59 % | 0.01 | 0.01 | Externo | Pilar C-30 - Retangular 20x40
P14 | COBERTURA | 2.5 | 20 | 40 | 0 | 0.59 % | 0.03 | 0.03 | Externo | Pilar C-30 - Retangular 20x40
P15 | COBERTURA | 2.5 | 14 | 30 | 0 | 1.75 % | 0.07 | 0.05 | Externo | Pilar C-30 - Retangular 14x30
P2 | COBERTURA | 2.5 | 20 | 30 | 0 | 1.23 % | 0.03 | 0.02 | Externo | Pilar C-30 - Retangular 20x30
P3 | COBERTURA | 2.5 | 14 | 30 | 0 | 2.34 % | 0.03 | 0.02 | Externo | Pilar C-30 - Retangular 14x30
P4 | COBERTURA | 2.5 | 20 | 30 | 0 | 0.79 % | 0.03 | 0.02 | Externo | Pilar C-30 - Retangular 20x30
P41 | COBERTURA | 2.5 | 20 | 30 | 0 | 1.64 % | 0.16 | 0.13 | Externo | Pilar C-30 - Retangular 20x30
P42 | COBERTURA | 2.5 | 14 | 30 | 0 | 1.75 % | 0.03 | 0.02 | Externo | Pilar C-30 - Retangular 14x30
P43 | COBERTURA | 2.5 | 14 | 30 | 0 | 2.34 % | 0.02 | 0.01 | Externo | Pilar C-30 - Retangular 14x30
P44 | COBERTURA | 2.5 | 14 | 30 | 0 | 1.75 % | 0.03 | 0.02 | Externo | Pilar C-30 - Retangular 14x30
P45 | COBERTURA | 2.5 | 14 | 30 | 0 | 2.87 % | 0.05 | 0.03 | Externo | Pilar C-30 - Retangular 14x30
P5 | COBERTURA | 2.5 | 20 | 40 | 0 | 0.59 % | 0.01 | 0.01 | Externo | Pilar C-30 - Retangular 20x40
P6 | COBERTURA | 2.5 | 20 | 30 | 0 | 1.64 % | 0.08 | 0.07 | Externo | Pilar C-30 - Retangular 20x30
P9 | COBERTURA | 2.5 | 20 | 40 | 0 | 1.53 % | 0.09 | 0.07 | Externo | Pilar C-30 - Retangular 20x40

# IfcFooting (38)
Material: Concreto
Pset_ConcreteElementGeneral - ConcreteCover: 5 cm; ConstructionMethod: InSitu; ExposureClass: 2; StrengthClass: C-30
AltoQi_Eberick_Elemento - Elemento: Bloco; Elevação: 0 cm
AltoQi_Eberick_Padrão - Cobrimento: 5 cm; Classe de concreto: C-30
Pset_PileCommon - Reference: Estaca circular E40 - Concreto C-30
Pset_FootingCommon - Reference: Bloco C-30
Name | In | Tipo | Seção_LB (cm) | Seção_LH (cm)
P.A1 | PÁTIO | 4 RET | 1.7 | 1.7
P.A10 | PÁTIO | 4 RET | 1.7 | 1.7
P.A11 | PÁTIO | 4 RET | 1.7 | 1.7
P.A12 | PÁTIO | 4 RET | 1.7 | 1.7
P.A13 | PÁTIO | 3 TRI | 1.80829 | 1.56603
P.A14 | PÁTIO | 4 RET | 1.7 | 1.7
P.A15 | PÁTIO | 3 TRI | 1.80829 | 1.56603
P.A16 | PÁTIO | 4 RET | 1.7 | 1.7
P.A17 | PÁTIO | 3 TRI | 1.80829 | 1.56603
P.A2 | PÁTIO | 4 RET | 1.7 | 1.7
P.A3 | PÁTIO | 4 RET | 1.7 | 1.7
P.A4 | PÁTIO | 4 RET | 1.7 | 1.7
P.A5 | PÁTIO | 2 | 1.9 | 0.7
P.A6 | PÁTIO | 4 RET | 1.7 | 1.7
P.A7 | PÁTIO | 4 RET | 1.7 | 1.7
P.A8 | PÁTIO | 4 RET | 1.9 | 1.9
P.A9 | PÁTIO | 3 TRI | 1.80829 | 1.56603
P.MURO1 | PÁTIO | 1 | 0.7 | 0.7
P.MURO2 | PÁTIO | 1 | 0.7 | 0.7
P.MURO5 | PÁTIO | 1 | 0.7 | 0.7
P10 | PÁTIO | 2 | 1.7 | 0.7
P11 | PÁTIO | 3 TRI | 1.80829 | 1.56603
P12 | PÁTIO | 3 TRI | 1.80829 | 1.56603
P14 | PÁTIO | 3 TRI | 1.80829 | 1.56603
P15 | PÁTIO | 2 | 1.7 | 0.7
P18 | PÁTIO | 2 | 1.7 | 0.7
P19 | PÁTIO | 3 TRI | 1.80829 | 1.56603
P21 | PÁTIO | 3 TRI | 1.80829 | 1.56603
P22 | PÁTIO | 2 | 1.7 | 0.7
P23 | PÁTIO | 3 TRI | 1.80829 | 1.56603
P24 | PÁTIO | 3 TRI | 1.80829 | 1.56603
P25 | PÁTIO | 3 TRI | 1.80829 | 1.56603
P26 | PÁTIO | 2 | 1.7 | 0.7
P27 | PÁTIO | 2 | 1.7 | 0.7
P.MURO3 | TÉRREO | 1 | 0.7 | 0.7
P.MURO4 | TÉRREO | 1 | 0.7 | 0.7
P.MURO6 | TÉRREO | 1 | 0.7 | 0.7
P.RAMPA5 | TÉRREO | 1 | 0.7 | 0.7

# IfcPile (105)
Material: Concreto
Pset_ConcreteElementGeneral - ConcreteCover: 5 cm; ConstructionMethod: InSitu; ExposureClass: 2; StrengthClass: C-30
AltoQi_Eberick_Elemento - Elemento: Bloco; Elevação: 0 cm
AltoQi_Eberick_Padrão - Cobrimento: 5 cm; Classe de concreto: C-30
Pset_PileCommon - Reference: Estaca circular E40 - Concreto C-30
Pset_FootingCommon - Reference: Bloco C-30
Name | In | Tipo | Seção_LB (cm) | Seção_LH (cm)
E.A1-1 | PÁTIO | 4 RET | 1.7 | 1.7
E.A1-2 | PÁTIO | 4 RET | 1.7 | 1.7
E.A1-3 | PÁTIO | 4 RET | 1.7 | 1.7
E.A1-4 | PÁTIO | 4 RET | 1.7 | 1.7
E.A10-1 | PÁTIO | 4 RET | 1.7 | 1.7
E.A10-2 | PÁTIO | 4 RET | 1.7 | 1.7
E.A10-3 | PÁTIO | 4 RET | 1.7 | 1.7
E.A10-4 | PÁTIO | 4 RET | 1.7 | 1.7
E.A11-1 | PÁTIO | 4 RET | 1.7 | 1.7
E.A11-2 | PÁTIO | 4 RET | 1.7 | 1.7
E.A11-3 | PÁTIO | 4 RET | 1.7 | 1.7
E.A11-4 | PÁTIO | 4 RET | 1.7 | 1.7
E.A12-1 | PÁTIO | 4 RET | 1.7 | 1.7
E.A12-2 | PÁTIO | 4 RET | 1.7 | 1.7
E.A12-3 | PÁTIO | 4 RET | 1.7 | 1.7
E.A12-4 | PÁTIO | 4 RET | 1.7 | 1.7
E.A13-1 | PÁTIO | 3 TRI | 1.80829 | 1.56603
E.A13-2 | PÁTIO | 3 TRI | 1.80829 | 1.56603
E.A13-3 | PÁTIO | 3 TRI | 1.80829 | 1.56603
E.A14-1 | PÁTIO | 4 RET | 1.7 | 1.7
E.A14-2 | PÁTIO | 4 RET | 1.7 | 1.7
E.A14-3 | PÁTIO | 4 RET | 1.7 | 1.7
E.A14-4 | PÁTIO | 4 RET | 1.7 | 1.7
E.A15-1 | PÁTIO | 3 TRI | 1.80829 | 1.56603
E.A15-2 | PÁTIO | 3 TRI | 1.80829 | 1.56603
E.A15-3 | PÁTIO | 3 TRI | 1.80829 | 1.56603
E.A16-1 | PÁTIO | 4 RET | 1.7 | 1.7
E.A16-2 | PÁTIO | 4 RET | 1.7 | 1.7
E.A16-3 | PÁTIO | 4 RET | 1.7 | 1.7
E.A16-4 | PÁTIO | 4 RET | 1.7 | 1.7
E.A17-1 | PÁTIO | 3 TRI | 1.80829 | 1.56603
E.A17-2 | PÁTIO | 3 TRI | 1.80829 | 1.56603
E.A17-3 | PÁTIO | 3 TRI | 1.80829 | 1.56603
E.A2-1 | PÁTIO | 4 RET | 1.7 | 1.7
E.A2-2 | PÁTIO | 4 RET | 1.7 | 1.7
E.A2-3 | PÁTIO | 4 RET | 1.7 | 1.7
E.A2-4 | PÁTIO | 4 RET | 1.7 | 1.7
E.A3-1 | PÁTIO | 4 RET | 1.7 | 1.7
E.A3-2 | PÁTIO | 4 RET | 1.7 | 1.7
E.A3-3 | PÁTIO | 4 RET | 1.7 | 1.7
E.A3-4 | PÁTIO | 4 RET | 1.7 | 1.7
E.A4-1 | PÁTIO | 4 RET | 1.7 | 1.7
E.A4-2 | PÁTIO | 4 RET | 1.7 | 1.7
E.A4-3 | PÁTIO | 4 RET | 1.7 | 1.7
E.A4-4 | PÁTIO | 4 RET | 1.7 | 1.7
E.A5-1 | PÁTIO | 2 | 1.9 | 0.7
E.A5-2 | PÁTIO | 2 | 1.9 | 0.7
E.A6-1 | PÁTIO | 4 RET | 1.7 | 1.7
E.A6-2 | PÁTIO | 4 RET | 1.7 | 1.7
E.A6-3 | PÁTIO | 4 RET | 1.7 | 1.7
E.A6-4 | PÁTIO | 4 RET | 1.7 | 1.7
E.A7-1 | PÁTIO | 4 RET | 1.7 | 1.7
E.A7-2 | PÁTIO | 4 RET | 1.7 | 1.7
E.A7-3 | PÁTIO | 4 RET | 1.7 | 1.7
E.A7-4 | PÁTIO | 4 RET | 1.7 | 1.7
E.A8-1 | PÁTIO | 4 RET | 1.9 | 1.9
E.A8-2 | PÁTIO | 4 RET | 1.9 | 1.9
E.A8-3 | PÁTIO | 4 RET | 1.9 | 1.9
E.A8-4 | PÁTIO | 4 RET | 1.9 | 1.9
E.A9-1 | PÁTIO | 3 TRI | 1.80829 | 1.56603
E.A9-2 | PÁTIO | 3 TRI | 1.80829 | 1.56603
E.A9-3 | PÁTIO | 3 TRI | 1.80829 | 1.56603
E.MURO1-1 | PÁTIO | 1 | 0.7 | 0.7
E.MURO2-1 | PÁTIO | 1 | 0.7 | 0.7
E.MURO5-1 | PÁTIO | 1 | 0.7 | 0.7
E10-1 | PÁTIO | 2 | 1.7 | 0.7
E10-2 | PÁTIO | 2 | 1.7 | 0.7
E11-1 | PÁTIO | 3 TRI | 1.80829 | 1.56603
E11-2 | PÁTIO | 3 TRI | 1.80829 | 1.56603
E11-3 | PÁTIO | 3 TRI | 1.80829 | 1.56603
E12-1 | PÁTIO | 3 TRI | 1.80829 | 1.56603
E12-2 | PÁTIO | 3 TRI | 1.80829 | 1.56603
E12-3 | PÁTIO | 3 TRI | 1.80829 | 1.56603
E14-1 | PÁTIO | 3 TRI | 1.80829 | 1.56603
E14-2 | PÁTIO | 3 TRI | 1.80829 | 1.56603
E14-3 | PÁTIO | 3 TRI | 1.80829 | 1.56603
E15-1 | PÁTIO | 2 | 1.7 | 0.7
E15-2 | PÁTIO | 2 | 1.7 | 0.7
E18-1 | PÁTIO | 2 | 1.7 | 0.7
E18-2 | PÁTIO | 2 | 1.7 | 0.7
E19-1 | PÁTIO | 3 TRI | 1.80829 | 1.56603
E19-2 | PÁTIO | 3 TRI | 1.80829 | 1.56603
E19-3 | PÁTIO | 3 TRI | 1.80829 | 1.56603
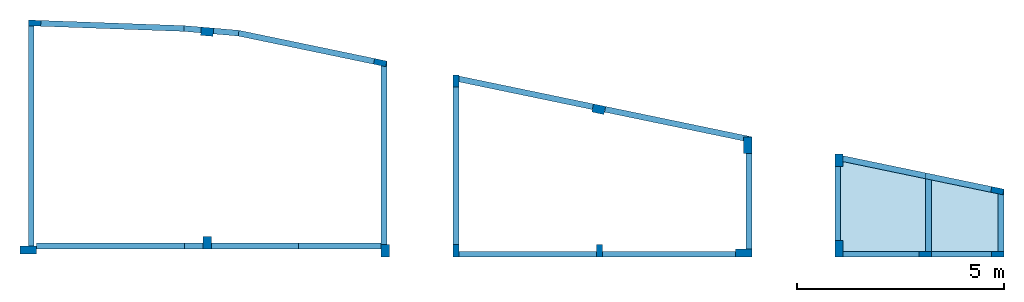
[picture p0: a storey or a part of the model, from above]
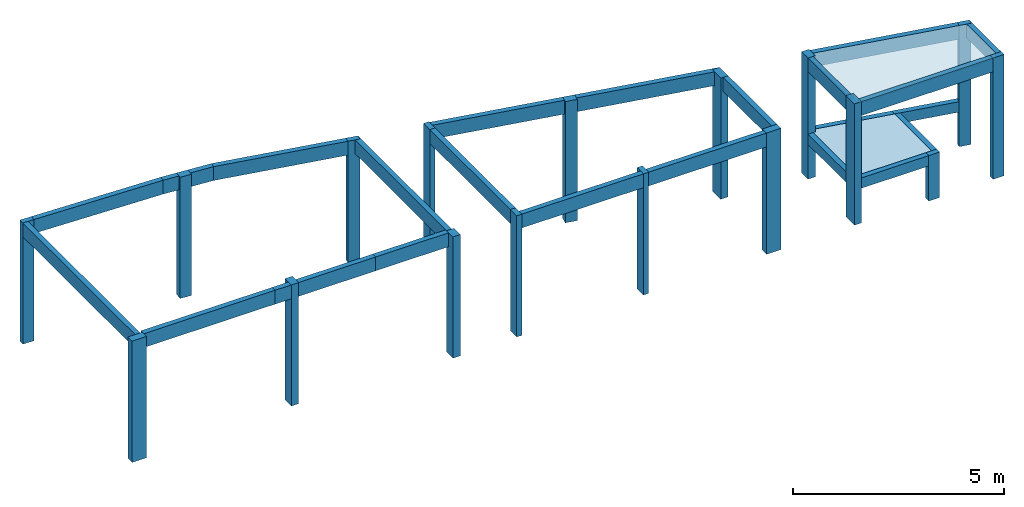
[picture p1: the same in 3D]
Properties of the parts of a building model (IFC4), part 2 of 2

# IfcPile (105)
Name | In | Tipo | Seção_LB (cm) | Seção_LH (cm)
E21-1 | PÁTIO | 3 TRI | 1.80829 | 1.56603
E21-2 | PÁTIO | 3 TRI | 1.80829 | 1.56603
E21-3 | PÁTIO | 3 TRI | 1.80829 | 1.56603
E22-1 | PÁTIO | 2 | 1.7 | 0.7
E22-2 | PÁTIO | 2 | 1.7 | 0.7
E23-1 | PÁTIO | 3 TRI | 1.80829 | 1.56603
E23-2 | PÁTIO | 3 TRI | 1.80829 | 1.56603
E23-3 | PÁTIO | 3 TRI | 1.80829 | 1.56603
E24-1 | PÁTIO | 3 TRI | 1.80829 | 1.56603
E24-2 | PÁTIO | 3 TRI | 1.80829 | 1.56603
E24-3 | PÁTIO | 3 TRI | 1.80829 | 1.56603
E25-1 | PÁTIO | 3 TRI | 1.80829 | 1.56603
E25-2 | PÁTIO | 3 TRI | 1.80829 | 1.56603
E25-3 | PÁTIO | 3 TRI | 1.80829 | 1.56603
E26-1 | PÁTIO | 2 | 1.7 | 0.7
E26-2 | PÁTIO | 2 | 1.7 | 0.7
E27-1 | PÁTIO | 2 | 1.7 | 0.7
E27-2 | PÁTIO | 2 | 1.7 | 0.7
E.MURO3-1 | TÉRREO | 1 | 0.7 | 0.7
E.MURO4-1 | TÉRREO | 1 | 0.7 | 0.7
E.MURO6-1 | TÉRREO | 1 | 0.7 | 0.7
E.RAMPA5-1 | TÉRREO | 1 | 0.7 | 0.7

# IfcRampFlight (3)
In: TÉRREO
Material: Concreto
Pset_ConcreteElementGeneral - ConcreteCover: 1.6 cm; ConstructionMethod: InSitu; ExposureClass: 2; StrengthClass: C-30
AltoQi_Eberick_Elemento - Elemento: Escada; Tipo: Rampa; Espessura: 20 cm; Piso: 0 cm; Espelho: 0 cm; Primeira_face: 0 cm
AltoQi_Eberick_Padrão - Ambiente: Externo; Cobrimento: 1.6 cm; Classe de concreto: C-30
AltoQi_Eberick_Cargas - Revestimento (G2): 154.5; Adicional (G2): 0; Solo (S): 0; Acidental (Q): 300; Água (A): 0; Subpressão (AS): 0
Pset_RampFlightCommon - Reference: Rampa Maciça - h=0.2m
Name
LE10
LE5
LE7

# IfcSlab (116)
Material: Concreto
Pset_ConcreteElementGeneral - ConstructionMethod: InSitu; ExposureClass: 2; StrengthClass: C-30
AltoQi_Eberick_Elemento - Tipo: Maciça
AltoQi_Eberick_Padrão - Classe de concreto: C-30
AltoQi_Eberick_Cargas - Adicional (G2): 0; Solo (S): 0; Água (A): 0; Subpressão (AS): 0
Pset_SlabCommon - LoadBearing: yes; IsExternal: yes; PitchAngle: 0 rad
Name | In | PredefinedType | ConcreteCover (cm) = Cobrimento (cm) | Elemento | Elevação (cm) | Espessura (cm) | Ambiente | Revestimento (G2) | Acidental (Q) | Reference
L1 | PÁTIO | FLOOR | 3 | Laje | 0 | 12 | Contato com solo | 50 | 50 | Laje Maciça - h=0.12m
L10 | PÁTIO | FLOOR | 3 | Laje | 0 | 12 | Contato com solo | 50 | 50 | Laje Maciça - h=0.12m
L11 | PÁTIO | FLOOR | 3 | Laje | 0 | 12 | Contato com solo | 50 | 50 | Laje Maciça - h=0.12m
L12 | PÁTIO | FLOOR | 3 | Laje | 0 | 12 | Contato com solo | 50 | 50 | Laje Maciça - h=0.12m
L13 | PÁTIO | FLOOR | 3 | Laje | 0 | 12 | Contato com solo | 50 | 50 | Laje Maciça - h=0.12m
L14 | PÁTIO | FLOOR | 3 | Laje | 0 | 12 | Contato com solo | 50 | 50 | Laje Maciça - h=0.12m
L15 | PÁTIO | FLOOR | 3 | Laje | 0 | 12 | Contato com solo | 50 | 50 | Laje Maciça - h=0.12m
L16 | PÁTIO | FLOOR | 3 | Laje | 0 | 12 | Contato com solo | 50 | 50 | Laje Maciça - h=0.12m
L17 | PÁTIO | FLOOR | 3 | Laje | 0 | 12 | Contato com solo | 50 | 50 | Laje Maciça - h=0.12m
L18 | PÁTIO | FLOOR | 3 | Laje | 0 | 12 | Contato com solo | 50 | 50 | Laje Maciça - h=0.12m
L19 | PÁTIO | FLOOR | 3 | Laje | 0 | 12 | Contato com solo | 50 | 50 | Laje Maciça - h=0.12m
L2 | PÁTIO | FLOOR | 3 | Laje | 0 | 12 | Contato com solo | 50 | 50 | Laje Maciça - h=0.12m
L20 | PÁTIO | FLOOR | 3 | Laje | 0 | 12 | Contato com solo | 50 | 50 | Laje Maciça - h=0.12m
L21 | PÁTIO | FLOOR | 3 | Laje | 0 | 12 | Contato com solo | 50 | 50 | Laje Maciça - h=0.12m
L22 | PÁTIO | FLOOR | 3 | Laje | 0 | 12 | Contato com solo | 50 | 50 | Laje Maciça - h=0.12m
L3 | PÁTIO | FLOOR | 3 | Laje | 0 | 12 | Contato com solo | 50 | 50 | Laje Maciça - h=0.12m
L4 | PÁTIO | FLOOR | 3 | Laje | 0 | 12 | Contato com solo | 50 | 50 | Laje Maciça - h=0.12m
L5 | PÁTIO | FLOOR | 3 | Laje | 0 | 12 | Contato com solo | 50 | 50 | Laje Maciça - h=0.12m
L6 | PÁTIO | FLOOR | 3 | Laje | 0 | 12 | Contato com solo | 50 | 50 | Laje Maciça - h=0.12m
L7 | PÁTIO | FLOOR | 1.6 | Laje | -150 | 20 | Externo | 136.5 | 750 | Laje Maciça - h=0.2m
L8 | PÁTIO | FLOOR | 3 | Laje | 0 | 12 | Contato com solo | 50 | 50 | Laje Maciça - h=0.12m
L9 | PÁTIO | FLOOR | 3 | Laje | 0 | 12 | Contato com solo | 50 | 50 | Laje Maciça - h=0.12m
L1 | TÉRREO | FLOOR | 1.6 | Laje | 0 | 15 | Externo | 154.5 | 300 | Laje Maciça - h=0.15m
L10 | TÉRREO | FLOOR | 1.6 | Laje | 0 | 15 | Externo | 154.5 | 300 | Laje Maciça - h=0.15m
L11 | TÉRREO | FLOOR | 1.6 | Laje | 0 | 15 | Externo | 154.5 | 300 | Laje Maciça - h=0.15m
L12 | TÉRREO | FLOOR | 1.6 | Laje | 0 | 15 | Externo | 154.5 | 300 | Laje Maciça - h=0.15m
L13 | TÉRREO | FLOOR | 1.6 | Laje | 0 | 15 | Externo | 154.5 | 300 | Laje Maciça - h=0.15m
L14 | TÉRREO | FLOOR | 1.6 | Laje | 0 | 15 | Externo | 154.5 | 300 | Laje Maciça - h=0.15m
L15 | TÉRREO | FLOOR | 1.6 | Laje | 0 | 15 | Externo | 154.5 | 300 | Laje Maciça - h=0.15m
L16 | TÉRREO | FLOOR | 1.6 | Laje | 0 | 15 | Externo | 154.5 | 300 | Laje Maciça - h=0.15m
L17 | TÉRREO | FLOOR | 1.6 | Laje | 0 | 15 | Externo | 154.5 | 300 | Laje Maciça - h=0.15m
L18 | TÉRREO | FLOOR | 1.6 | Laje | 0 | 15 | Externo | 154.5 | 300 | Laje Maciça - h=0.15m
L19 | TÉRREO | FLOOR | 1.6 | Laje | 0 | 15 | Externo | 154.5 | 300 | Laje Maciça - h=0.15m
L2 | TÉRREO | FLOOR | 1.6 | Laje | 0 | 15 | Externo | 154.5 | 300 | Laje Maciça - h=0.15m
L20 | TÉRREO | FLOOR | 1.6 | Laje | 0 | 15 | Externo | 154.5 | 300 | Laje Maciça - h=0.15m
L21 | TÉRREO | FLOOR | 1.6 | Laje | 0 | 22 | Externo | 154.5 | 300 | Laje Maciça - h=0.22m
L22 | TÉRREO | FLOOR | 1.6 | Laje | 0 | 15 | Externo | 154.5 | 300 | Laje Maciça - h=0.15m
L3 | TÉRREO | FLOOR | 1.6 | Laje | 0 | 15 | Externo | 154.5 | 300 | Laje Maciça - h=0.15m
L4 | TÉRREO | FLOOR | 1.6 | Laje | 0 | 15 | Externo | 154.5 | 300 | Laje Maciça - h=0.15m
L5 | TÉRREO | FLOOR | 1.6 | Laje | 0 | 15 | Externo | 154.5 | 300 | Laje Maciça - h=0.15m
L6 | TÉRREO | FLOOR | 1.6 | Laje | 0 | 15 | Externo | 154.5 | 300 | Laje Maciça - h=0.15m
L7 | TÉRREO | FLOOR | 1.6 | Laje | 0 | 15 | Externo | 154.5 | 300 | Laje Maciça - h=0.15m
L8 | TÉRREO | FLOOR | 1.6 | Laje | 0 | 15 | Externo | 154.5 | 300 | Laje Maciça - h=0.15m
L9 | TÉRREO | FLOOR | 1.6 | Laje | 0 | 15 | Externo | 154.5 | 300 | Laje Maciça - h=0.15m
LE11 | TÉRREO | LANDING | 1.6 | Patamar de escada | 0 | 20 | Externo | 154.5 | 300 | Patamar de escada C-30 - h=0.2m
LE2 | TÉRREO | LANDING | 1.6 | Patamar de escada | -17.7 | 25 | Externo | 154.5 | 300 | Patamar de escada C-30 - h=0.25m
LE3 | TÉRREO | LANDING | 1.6 | Patamar de escada | 0 | 25 | Externo | 154.5 | 300 | Patamar de escada C-30 - h=0.25m
LE6 | TÉRREO | LANDING | 1.6 | Patamar de escada | 0 | 20 | Externo | 154.5 | 300 | Patamar de escada C-30 - h=0.2m
LE8 | TÉRREO | LANDING | 1.6 | Patamar de escada | 0 | 20 | Externo | 154.5 | 300 | Patamar de escada C-30 - h=0.2m
L1 | 1º PAV. | FLOOR | 1.6 | Laje | 0 | 15 | Externo | 154.5 | 300 | Laje Maciça - h=0.15m
L10 | 1º PAV. | FLOOR | 1.6 | Laje | 0 | 18 | Externo | 154.5 | 300 | Laje Maciça - h=0.18m
L11 | 1º PAV. | FLOOR | 1.6 | Laje | 0 | 15 | Externo | 154.5 | 300 | Laje Maciça - h=0.15m
L12 | 1º PAV. | FLOOR | 1.6 | Laje | 0 | 15 | Externo | 154.5 | 300 | Laje Maciça - h=0.15m
L13 | 1º PAV. | FLOOR | 1.6 | Laje | 0 | 15 | Externo | 154.5 | 300 | Laje Maciça - h=0.15m
L14 | 1º PAV. | FLOOR | 1.6 | Laje | 0 | 15 | Externo | 154.5 | 300 | Laje Maciça - h=0.15m
L15 | 1º PAV. | FLOOR | 1.6 | Laje | 0 | 15 | Externo | 154.5 | 300 | Laje Maciça - h=0.15m
L16 | 1º PAV. | FLOOR | 1.6 | Laje | 0 | 17 | Externo | 154.5 | 300 | Laje Maciça - h=0.17m
L17 | 1º PAV. | FLOOR | 1.6 | Laje | 0 | 17 | Externo | 154.5 | 300 | Laje Maciça - h=0.17m
L18 | 1º PAV. | FLOOR | 1.6 | Laje | 0 | 15 | Externo | 154.5 | 300 | Laje Maciça - h=0.15m
L19 | 1º PAV. | FLOOR | 1.6 | Laje | 0 | 18 | Externo | 154.5 | 300 | Laje Maciça - h=0.18m
L2 | 1º PAV. | FLOOR | 1.6 | Laje | 0 | 15 | Externo | 154.5 | 300 | Laje Maciça - h=0.15m
L20 | 1º PAV. | FLOOR | 1.6 | Laje | 0 | 15 | Externo | 154.5 | 300 | Laje Maciça - h=0.15m
L21 | 1º PAV. | FLOOR | 1.6 | Laje | 0 | 15 | Externo | 154.5 | 300 | Laje Maciça - h=0.15m
L22 | 1º PAV. | FLOOR | 1.6 | Laje | 0 | 18 | Externo | 154.5 | 300 | Laje Maciça - h=0.18m
L23 | 1º PAV. | FLOOR | 1.6 | Laje | 0 | 22 | Externo | 154.5 | 300 | Laje Maciça - h=0.22m
L3 | 1º PAV. | FLOOR | 1.6 | Laje | 0 | 15 | Externo | 154.5 | 300 | Laje Maciça - h=0.15m
L4 | 1º PAV. | FLOOR | 1.6 | Laje | 0 | 15 | Externo | 154.5 | 300 | Laje Maciça - h=0.15m
L5 | 1º PAV. | FLOOR | 1.6 | Laje | 0 | 15 | Externo | 154.5 | 300 | Laje Maciça - h=0.15m
L6 | 1º PAV. | FLOOR | 1.6 | Laje | 0 | 15 | Externo | 154.5 | 300 | Laje Maciça - h=0.15m
L7 | 1º PAV. | FLOOR | 1.6 | Laje | 0 | 15 | Externo | 154.5 | 300 | Laje Maciça - h=0.15m
L8 | 1º PAV. | FLOOR | 1.6 | Laje | 0 | 15 | Externo | 154.5 | 300 | Laje Maciça - h=0.15m
L9 | 1º PAV. | FLOOR | 1.6 | Laje | 0 | 15 | Externo | 154.5 | 300 | Laje Maciça - h=0.15m
LE2 | 1º PAV. | LANDING | 1.6 | Patamar de escada | -17.5 | 15 | Externo | 154.5 | 300 | Patamar de escada C-30 - h=0.15m
LE3 | 1º PAV. | LANDING | 1.6 | Patamar de escada | 0 | 15 | Externo | 154.5 | 300 | Patamar de escada C-30 - h=0.15m
L1 | 2º PAV. | FLOOR | 1.6 | Laje | 0 | 15 | Externo | 181.5 | 200 | Laje Maciça - h=0.15m
L10 | 2º PAV. | FLOOR | 1.6 | Laje | 0 | 20 | Externo | 154.5 | 500 | Laje Maciça - h=0.2m
L11 | 2º PAV. | FLOOR | 1.6 | Laje | 0 | 20 | Externo | 181.5 | 200 | Laje Maciça - h=0.2m
L12 | 2º PAV. | FLOOR | 1.6 | Laje | 0 | 20 | Externo | 154.5 | 500 | Laje Maciça - h=0.2m
L13 | 2º PAV. | FLOOR | 1.6 | Laje | 0 | 20 | Externo | 154.5 | 500 | Laje Maciça - h=0.2m
L14 | 2º PAV. | FLOOR | 1.6 | Laje | 0 | 15 | Externo | 154.5 | 500 | Laje Maciça - h=0.15m
L15 | 2º PAV. | FLOOR | 1.6 | Laje | 0 | 15 | Externo | 154.5 | 300 | Laje Maciça - h=0.15m
L16 | 2º PAV. | FLOOR | 1.6 | Laje | 0 | 15 | Externo | 154.5 | 300 | Laje Maciça - h=0.15m
L17 | 2º PAV. | FLOOR | 1.6 | Laje | 0 | 15 | Externo | 154.5 | 300 | Laje Maciça - h=0.15m
L18 | 2º PAV. | FLOOR | 1.6 | Laje | 0 | 15 | Externo | 154.5 | 500 | Laje Maciça - h=0.15m
L19 | 2º PAV. | FLOOR | 1.6 | Laje | 0 | 20 | Externo | 154.5 | 500 | Laje Maciça - h=0.2m
L2 | 2º PAV. | FLOOR | 1.6 | Laje | 0 | 15 | Externo | 181.5 | 200 | Laje Maciça - h=0.15m
L20 | 2º PAV. | FLOOR | 1.6 | Laje | 0 | 20 | Externo | 154.5 | 500 | Laje Maciça - h=0.2m
L21 | 2º PAV. | FLOOR | 1.6 | Laje | 0 | 20 | Externo | 154.5 | 500 | Laje Maciça - h=0.2m
L22 | 2º PAV. | FLOOR | 1.6 | Laje | 0 | 20 | Externo | 154.5 | 500 | Laje Maciça - h=0.2m
L23 | 2º PAV. | FLOOR | 1.6 | Laje | 0 | 22 | Externo | 154.5 | 300 | Laje Maciça - h=0.22m
L3 | 2º PAV. | FLOOR | 1.6 | Laje | 0 | 15 | Externo | 154.5 | 300 | Laje Maciça - h=0.15m
L4 | 2º PAV. | FLOOR | 1.6 | Laje | 0 | 15 | Externo | 154.5 | 300 | Laje Maciça - h=0.15m
L5 | 2º PAV. | FLOOR | 1.6 | Laje | 0 | 15 | Externo | 154.5 | 300 | Laje Maciça - h=0.15m
L6 | 2º PAV. | FLOOR | 1.6 | Laje | 0 | 15 | Externo | 154.5 | 300 | Laje Maciça - h=0.15m
L7 | 2º PAV. | FLOOR | 1.6 | Laje | 0 | 15 | Externo | 154.5 | 300 | Laje Maciça - h=0.15m
L8 | 2º PAV. | FLOOR | 1.6 | Laje | 0 | 15 | Externo | 154.5 | 300 | Laje Maciça - h=0.15m
L9 | 2º PAV. | FLOOR | 1.6 | Laje | 0 | 15 | Externo | 154.5 | 500 | Laje Maciça - h=0.15m
LE2 | 2º PAV. | LANDING | 1.6 | Patamar de escada | -17.5 | 15 | Externo | 154.5 | 300 | Patamar de escada C-30 - h=0.15m
LE3 | 2º PAV. | LANDING | 1.6 | Patamar de escada | 0 | 15 | Externo | 154.5 | 300 | Patamar de escada C-30 - h=0.15m
L1 | 3º PAV. | FLOOR | 1.6 | Laje | 0 | 20 | Externo | 181.5 | 100 | Laje Maciça - h=0.2m
L10 | 3º PAV. | FLOOR | 1.6 | Laje | 0 | 15 | Externo | 181.5 | 100 | Laje Maciça - h=0.15m
L11 | 3º PAV. | FLOOR | 1.6 | Laje | 0 | 15 | Externo | 181.5 | 100 | Laje Maciça - h=0.15m
L12 | 3º PAV. | FLOOR | 1.6 | Laje | 0 | 15 | Externo | 181.5 | 100 | Laje Maciça - h=0.15m
L13 | 3º PAV. | FLOOR | 1.6 | Laje | 0 | 15 | Externo | 181.5 | 100 | Laje Maciça - h=0.15m
L14 | 3º PAV. | FLOOR | 1.6 | Laje | 0 | 15 | Externo | 181.5 | 100 | Laje Maciça - h=0.15m
L15 | 3º PAV. | FLOOR | 1.6 | Laje | 0 | 15 | Externo | 181.5 | 100 | Laje Maciça - h=0.15m
L2 | 3º PAV. | FLOOR | 1.6 | Laje | 0 | 20 | Externo | 181.5 | 100 | Laje Maciça - h=0.2m
L3 | 3º PAV. | FLOOR | 1.6 | Laje | 0 | 15 | Externo | 181.5 | 100 | Laje Maciça - h=0.15m
L4 | 3º PAV. | FLOOR | 1.6 | Laje | 0 | 15 | Externo | 181.5 | 100 | Laje Maciça - h=0.15m
L5 | 3º PAV. | FLOOR | 1.6 | Laje | 0 | 20 | Externo | 181.5 | 100 | Laje Maciça - h=0.2m
L6 | 3º PAV. | FLOOR | 1.6 | Laje | 0 | 20 | Externo | 181.5 | 100 | Laje Maciça - h=0.2m
L7 | 3º PAV. | FLOOR | 1.6 | Laje | 0 | 15 | Externo | 136.5 | 750 | Laje Maciça - h=0.15m
L8 | 3º PAV. | FLOOR | 1.6 | Laje | 0 | 15 | Externo | 181.5 | 200 | Laje Maciça - h=0.15m
L9 | 3º PAV. | FLOOR | 1.6 | Laje | 0 | 15 | Externo | 181.5 | 100 | Laje Maciça - h=0.15m
L1 | COBERTURA | FLOOR | 1.6 | Laje | 0 | 15 | Externo | 136.5 | 750 | Laje Maciça - h=0.15m
L2 | COBERTURA | FLOOR | 1.6 | Laje | 0 | 15 | Externo | 136.5 | 750 | Laje Maciça - h=0.15m

# IfcStairFlight (7)
NumberOfRisers: 0; NumberOfTreads: 0; Material: Concreto
Pset_ConcreteElementGeneral - ConcreteCover: 1.6 cm; ConstructionMethod: InSitu; ExposureClass: 2; StrengthClass: C-30
AltoQi_Eberick_Elemento - Elemento: Escada; Tipo: Fundo plano; Piso: 28 cm
AltoQi_Eberick_Padrão - Ambiente: Externo; Cobrimento: 1.6 cm; Classe de concreto: C-30
AltoQi_Eberick_Cargas - Revestimento (G2): 154.5; Adicional (G2): 0; Solo (S): 0; Acidental (Q): 300; Água (A): 0; Subpressão (AS): 0
Pset_StairFlightCommon - TreadLength: 28 cm
Name | In | Espessura (cm) = WaistThickness (cm) | Espelho (cm) = RiserHeight (cm) | Primeira_face (cm) | Reference
LE1 | TÉRREO | 25 | 17 | 0 | Lance de escada C-30 - Fundo plano - h= 0.25m
LE4 | TÉRREO | 25 | 17.7 | 0 | Lance de escada C-30 - Fundo plano - h= 0.25m
LE9 | TÉRREO | 15 | 17 | 0 | Lance de escada C-30 - Fundo plano - h= 0.15m
LE1 | 1º PAV. | 15 | 17.5 | 0 | Lance de escada C-30 - Fundo plano - h= 0.15m
LE4 | 1º PAV. | 15 | 17.5 | 27 | Lance de escada C-30 - Fundo plano - h= 0.15m
LE1 | 2º PAV. | 15 | 17.5 | 0 | Lance de escada C-30 - Fundo plano - h= 0.15m
LE4 | 2º PAV. | 15 | 17.5 | 27 | Lance de escada C-30 - Fundo plano - h= 0.15m

# IfcWall (56)
PredefinedType: SHEAR; Material: Concreto
Pset_ConcreteElementGeneral - ConcreteCover: 2.5 cm; ConstructionMethod: InSitu; ExposureClass: 2; StrengthClass: C-30
Pset_WallCommon - Reference: Parede de Contenção C-30 - e=0.2m; LoadBearing: yes
Name | In | Elemento
PAR1 | PÁTIO | PAR1
PAR10-A | PÁTIO | PAR10-A
PAR10-B | PÁTIO | PAR10-B
PAR10-C | PÁTIO | PAR10-C
PAR10-D | PÁTIO | PAR10-D
PAR2 | PÁTIO | PAR2
PAR3-A | PÁTIO | PAR3-A
PAR3-B | PÁTIO | PAR3-B
PAR4-A | PÁTIO | PAR4-A
PAR4-B | PÁTIO | PAR4-B
PAR4-C | PÁTIO | PAR4-C
PAR5-A | PÁTIO | PAR5-A
PAR5-B | PÁTIO | PAR5-B
PAR6-A | PÁTIO | PAR6-A
PAR6-B | PÁTIO | PAR6-B
PAR6-C | PÁTIO | PAR6-C
PAR6-D | PÁTIO | PAR6-D
PAR7-A | PÁTIO | PAR7-A
PAR7-B | PÁTIO | PAR7-B
PAR7-C | PÁTIO | PAR7-C
PAR8-A | PÁTIO | PAR8-A
PAR8-B | PÁTIO | PAR8-B
PAR9 | PÁTIO | PAR9
PAR1 | TÉRREO | PAR1
PAR10-A | TÉRREO | PAR10-A
PAR10-B | TÉRREO | PAR10-B
PAR10-C | TÉRREO | PAR10-C
PAR10-D | TÉRREO | PAR10-D
2 x PAR2 | TÉRREO | PAR2
PAR3-A | TÉRREO | PAR3-A
PAR3-B | TÉRREO | PAR3-B
PAR4-A | TÉRREO | PAR4-A
PAR4-B | TÉRREO | PAR4-B
PAR4-C | TÉRREO | PAR4-C
PAR5-A | TÉRREO | PAR5-A
PAR5-B | TÉRREO | PAR5-B
2 x PAR6-A | TÉRREO | PAR6-A
2 x PAR6-B | TÉRREO | PAR6-B
2 x PAR6-C | TÉRREO | PAR6-C
2 x PAR6-D | TÉRREO | PAR6-D
2 x PAR7-A | TÉRREO | PAR7-A
2 x PAR7-B | TÉRREO | PAR7-B
2 x PAR7-C | TÉRREO | PAR7-C
2 x PAR8-A | TÉRREO | PAR8-A
2 x PAR8-B | TÉRREO | PAR8-B
PAR9 | TÉRREO | PAR9
